VERSION 5.8 ;
BUSBITCHARS "[]" ;
DIVIDERCHAR "/" ;
UNITS
    DATABASE MICRONS 1000 ;
END UNITS

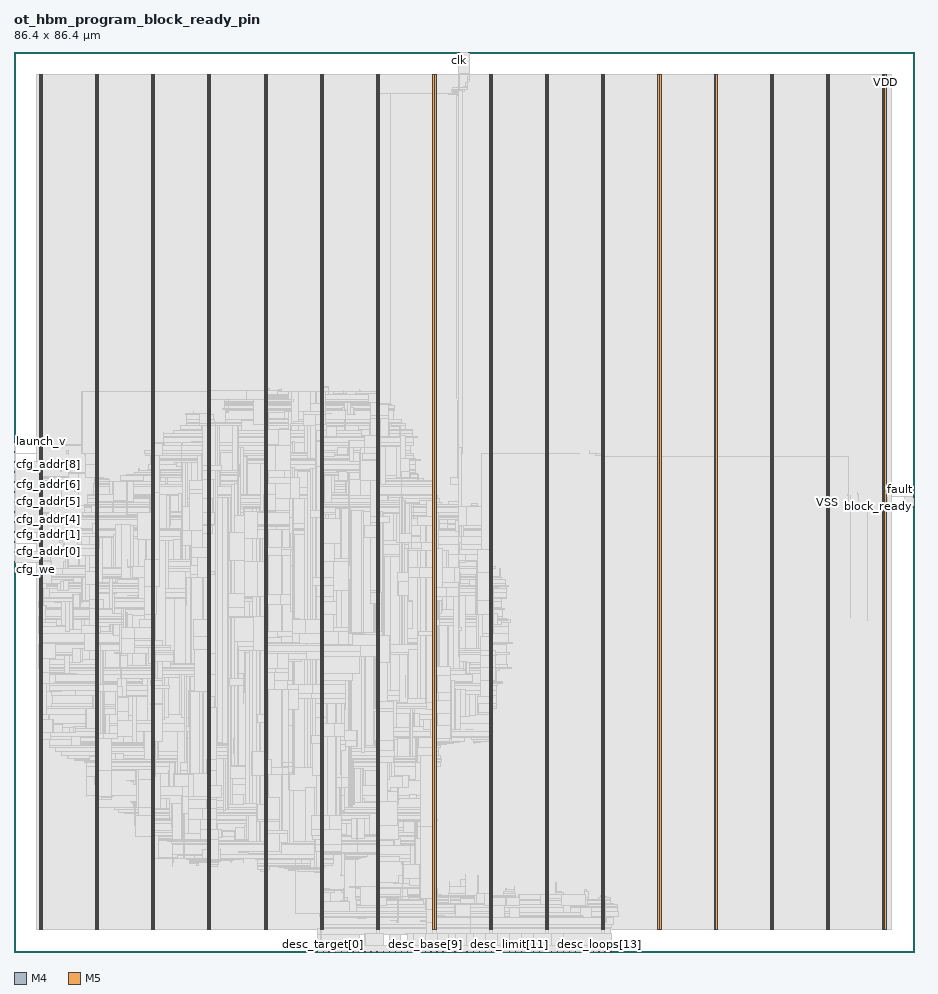
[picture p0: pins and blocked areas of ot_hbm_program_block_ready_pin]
MACRO ot_hbm_program_block_ready_pin
  FOREIGN ot_hbm_program_block_ready_pin 0 0 ;
  CLASS BLOCK ;
  SIZE 86.4 BY 86.4 ;
  PIN block_ready
    DIRECTION OUTPUT ;
    USE SIGNAL ;
    PORT
      LAYER M4 ;
        RECT  86.316 42.72 86.4 42.744 ;
    END
  END block_ready
  PIN cfg_addr[0]
    DIRECTION INPUT ;
    USE SIGNAL ;
    PORT
      LAYER M4 ;
        RECT  0 38.4 0.084 38.424 ;
    END
  END cfg_addr[0]
  PIN cfg_addr[1]
    DIRECTION INPUT ;
    USE SIGNAL ;
    PORT
      LAYER M4 ;
        RECT  0 39.36 0.084 39.384 ;
    END
  END cfg_addr[1]
  PIN cfg_addr[2]
    DIRECTION INPUT ;
    USE SIGNAL ;
    PORT
      LAYER M4 ;
        RECT  0 40.32 0.084 40.344 ;
    END
  END cfg_addr[2]
  PIN cfg_addr[3]
    DIRECTION INPUT ;
    USE SIGNAL ;
    PORT
      LAYER M4 ;
        RECT  0 41.28 0.084 41.304 ;
    END
  END cfg_addr[3]
  PIN cfg_addr[4]
    DIRECTION INPUT ;
    USE SIGNAL ;
    PORT
      LAYER M4 ;
        RECT  0 42.24 0.084 42.264 ;
    END
  END cfg_addr[4]
  PIN cfg_addr[5]
    DIRECTION INPUT ;
    USE SIGNAL ;
    PORT
      LAYER M4 ;
        RECT  0 43.2 0.084 43.224 ;
    END
  END cfg_addr[5]
  PIN cfg_addr[6]
    DIRECTION INPUT ;
    USE SIGNAL ;
    PORT
      LAYER M4 ;
        RECT  0 44.16 0.084 44.184 ;
    END
  END cfg_addr[6]
  PIN cfg_addr[7]
    DIRECTION INPUT ;
    USE SIGNAL ;
    PORT
      LAYER M4 ;
        RECT  0 45.12 0.084 45.144 ;
    END
  END cfg_addr[7]
  PIN cfg_addr[8]
    DIRECTION INPUT ;
    USE SIGNAL ;
    PORT
      LAYER M4 ;
        RECT  0 46.08 0.084 46.104 ;
    END
  END cfg_addr[8]
  PIN cfg_addr[9]
    DIRECTION INPUT ;
    USE SIGNAL ;
    PORT
      LAYER M4 ;
        RECT  0 47.04 0.084 47.064 ;
    END
  END cfg_addr[9]
  PIN cfg_we
    DIRECTION INPUT ;
    USE SIGNAL ;
    PORT
      LAYER M4 ;
        RECT  0 37.44 0.084 37.464 ;
    END
  END cfg_we
  PIN clk
    DIRECTION INPUT ;
    USE SIGNAL ;
    PORT
      LAYER M5 ;
        RECT  42.72 86.316 42.744 86.4 ;
    END
  END clk
  PIN desc_base[0]
    DIRECTION INPUT ;
    USE SIGNAL ;
    PORT
      LAYER M5 ;
        RECT  34.272 0 34.296 0.084 ;
    END
  END desc_base[0]
  PIN desc_base[10]
    DIRECTION INPUT ;
    USE SIGNAL ;
    PORT
      LAYER M5 ;
        RECT  40.032 0 40.056 0.084 ;
    END
  END desc_base[10]
  PIN desc_base[11]
    DIRECTION INPUT ;
    USE SIGNAL ;
    PORT
      LAYER M5 ;
        RECT  40.608 0 40.632 0.084 ;
    END
  END desc_base[11]
  PIN desc_base[1]
    DIRECTION INPUT ;
    USE SIGNAL ;
    PORT
      LAYER M5 ;
        RECT  34.848 0 34.872 0.084 ;
    END
  END desc_base[1]
  PIN desc_base[2]
    DIRECTION INPUT ;
    USE SIGNAL ;
    PORT
      LAYER M5 ;
        RECT  35.424 0 35.448 0.084 ;
    END
  END desc_base[2]
  PIN desc_base[3]
    DIRECTION INPUT ;
    USE SIGNAL ;
    PORT
      LAYER M5 ;
        RECT  36 0 36.024 0.084 ;
    END
  END desc_base[3]
  PIN desc_base[4]
    DIRECTION INPUT ;
    USE SIGNAL ;
    PORT
      LAYER M5 ;
        RECT  36.576 0 36.6 0.084 ;
    END
  END desc_base[4]
  PIN desc_base[5]
    DIRECTION INPUT ;
    USE SIGNAL ;
    PORT
      LAYER M5 ;
        RECT  37.152 0 37.176 0.084 ;
    END
  END desc_base[5]
  PIN desc_base[6]
    DIRECTION INPUT ;
    USE SIGNAL ;
    PORT
      LAYER M5 ;
        RECT  37.728 0 37.752 0.084 ;
    END
  END desc_base[6]
  PIN desc_base[7]
    DIRECTION INPUT ;
    USE SIGNAL ;
    PORT
      LAYER M5 ;
        RECT  38.304 0 38.328 0.084 ;
    END
  END desc_base[7]
  PIN desc_base[8]
    DIRECTION INPUT ;
    USE SIGNAL ;
    PORT
      LAYER M5 ;
        RECT  38.88 0 38.904 0.084 ;
    END
  END desc_base[8]
  PIN desc_base[9]
    DIRECTION INPUT ;
    USE SIGNAL ;
    PORT
      LAYER M5 ;
        RECT  39.456 0 39.48 0.084 ;
    END
  END desc_base[9]
  PIN desc_limit[0]
    DIRECTION INPUT ;
    USE SIGNAL ;
    PORT
      LAYER M5 ;
        RECT  41.184 0 41.208 0.084 ;
    END
  END desc_limit[0]
  PIN desc_limit[10]
    DIRECTION INPUT ;
    USE SIGNAL ;
    PORT
      LAYER M5 ;
        RECT  46.944 0 46.968 0.084 ;
    END
  END desc_limit[10]
  PIN desc_limit[11]
    DIRECTION INPUT ;
    USE SIGNAL ;
    PORT
      LAYER M5 ;
        RECT  47.52 0 47.544 0.084 ;
    END
  END desc_limit[11]
  PIN desc_limit[12]
    DIRECTION INPUT ;
    USE SIGNAL ;
    PORT
      LAYER M5 ;
        RECT  48.096 0 48.12 0.084 ;
    END
  END desc_limit[12]
  PIN desc_limit[1]
    DIRECTION INPUT ;
    USE SIGNAL ;
    PORT
      LAYER M5 ;
        RECT  41.76 0 41.784 0.084 ;
    END
  END desc_limit[1]
  PIN desc_limit[2]
    DIRECTION INPUT ;
    USE SIGNAL ;
    PORT
      LAYER M5 ;
        RECT  42.336 0 42.36 0.084 ;
    END
  END desc_limit[2]
  PIN desc_limit[3]
    DIRECTION INPUT ;
    USE SIGNAL ;
    PORT
      LAYER M5 ;
        RECT  42.912 0 42.936 0.084 ;
    END
  END desc_limit[3]
  PIN desc_limit[4]
    DIRECTION INPUT ;
    USE SIGNAL ;
    PORT
      LAYER M5 ;
        RECT  43.488 0 43.512 0.084 ;
    END
  END desc_limit[4]
  PIN desc_limit[5]
    DIRECTION INPUT ;
    USE SIGNAL ;
    PORT
      LAYER M5 ;
        RECT  44.064 0 44.088 0.084 ;
    END
  END desc_limit[5]
  PIN desc_limit[6]
    DIRECTION INPUT ;
    USE SIGNAL ;
    PORT
      LAYER M5 ;
        RECT  44.64 0 44.664 0.084 ;
    END
  END desc_limit[6]
  PIN desc_limit[7]
    DIRECTION INPUT ;
    USE SIGNAL ;
    PORT
      LAYER M5 ;
        RECT  45.216 0 45.24 0.084 ;
    END
  END desc_limit[7]
  PIN desc_limit[8]
    DIRECTION INPUT ;
    USE SIGNAL ;
    PORT
      LAYER M5 ;
        RECT  45.792 0 45.816 0.084 ;
    END
  END desc_limit[8]
  PIN desc_limit[9]
    DIRECTION INPUT ;
    USE SIGNAL ;
    PORT
      LAYER M5 ;
        RECT  46.368 0 46.392 0.084 ;
    END
  END desc_limit[9]
  PIN desc_loops[0]
    DIRECTION INPUT ;
    USE SIGNAL ;
    PORT
      LAYER M5 ;
        RECT  48.672 0 48.696 0.084 ;
    END
  END desc_loops[0]
  PIN desc_loops[10]
    DIRECTION INPUT ;
    USE SIGNAL ;
    PORT
      LAYER M5 ;
        RECT  54.432 0 54.456 0.084 ;
    END
  END desc_loops[10]
  PIN desc_loops[11]
    DIRECTION INPUT ;
    USE SIGNAL ;
    PORT
      LAYER M5 ;
        RECT  55.008 0 55.032 0.084 ;
    END
  END desc_loops[11]
  PIN desc_loops[12]
    DIRECTION INPUT ;
    USE SIGNAL ;
    PORT
      LAYER M5 ;
        RECT  55.584 0 55.608 0.084 ;
    END
  END desc_loops[12]
  PIN desc_loops[13]
    DIRECTION INPUT ;
    USE SIGNAL ;
    PORT
      LAYER M5 ;
        RECT  56.16 0 56.184 0.084 ;
    END
  END desc_loops[13]
  PIN desc_loops[14]
    DIRECTION INPUT ;
    USE SIGNAL ;
    PORT
      LAYER M5 ;
        RECT  56.736 0 56.76 0.084 ;
    END
  END desc_loops[14]
  PIN desc_loops[15]
    DIRECTION INPUT ;
    USE SIGNAL ;
    PORT
      LAYER M5 ;
        RECT  57.312 0 57.336 0.084 ;
    END
  END desc_loops[15]
  PIN desc_loops[1]
    DIRECTION INPUT ;
    USE SIGNAL ;
    PORT
      LAYER M5 ;
        RECT  49.248 0 49.272 0.084 ;
    END
  END desc_loops[1]
  PIN desc_loops[2]
    DIRECTION INPUT ;
    USE SIGNAL ;
    PORT
      LAYER M5 ;
        RECT  49.824 0 49.848 0.084 ;
    END
  END desc_loops[2]
  PIN desc_loops[3]
    DIRECTION INPUT ;
    USE SIGNAL ;
    PORT
      LAYER M5 ;
        RECT  50.4 0 50.424 0.084 ;
    END
  END desc_loops[3]
  PIN desc_loops[4]
    DIRECTION INPUT ;
    USE SIGNAL ;
    PORT
      LAYER M5 ;
        RECT  50.976 0 51 0.084 ;
    END
  END desc_loops[4]
  PIN desc_loops[5]
    DIRECTION INPUT ;
    USE SIGNAL ;
    PORT
      LAYER M5 ;
        RECT  51.552 0 51.576 0.084 ;
    END
  END desc_loops[5]
  PIN desc_loops[6]
    DIRECTION INPUT ;
    USE SIGNAL ;
    PORT
      LAYER M5 ;
        RECT  52.128 0 52.152 0.084 ;
    END
  END desc_loops[6]
  PIN desc_loops[7]
    DIRECTION INPUT ;
    USE SIGNAL ;
    PORT
      LAYER M5 ;
        RECT  52.704 0 52.728 0.084 ;
    END
  END desc_loops[7]
  PIN desc_loops[8]
    DIRECTION INPUT ;
    USE SIGNAL ;
    PORT
      LAYER M5 ;
        RECT  53.28 0 53.304 0.084 ;
    END
  END desc_loops[8]
  PIN desc_loops[9]
    DIRECTION INPUT ;
    USE SIGNAL ;
    PORT
      LAYER M5 ;
        RECT  53.856 0 53.88 0.084 ;
    END
  END desc_loops[9]
  PIN desc_target[0]
    DIRECTION INPUT ;
    USE SIGNAL ;
    PORT
      LAYER M5 ;
        RECT  29.664 0 29.688 0.084 ;
    END
  END desc_target[0]
  PIN desc_target[1]
    DIRECTION INPUT ;
    USE SIGNAL ;
    PORT
      LAYER M5 ;
        RECT  30.24 0 30.264 0.084 ;
    END
  END desc_target[1]
  PIN desc_target[2]
    DIRECTION INPUT ;
    USE SIGNAL ;
    PORT
      LAYER M5 ;
        RECT  30.816 0 30.84 0.084 ;
    END
  END desc_target[2]
  PIN desc_target[3]
    DIRECTION INPUT ;
    USE SIGNAL ;
    PORT
      LAYER M5 ;
        RECT  31.392 0 31.416 0.084 ;
    END
  END desc_target[3]
  PIN desc_target[4]
    DIRECTION INPUT ;
    USE SIGNAL ;
    PORT
      LAYER M5 ;
        RECT  31.968 0 31.992 0.084 ;
    END
  END desc_target[4]
  PIN desc_target[5]
    DIRECTION INPUT ;
    USE SIGNAL ;
    PORT
      LAYER M5 ;
        RECT  32.544 0 32.568 0.084 ;
    END
  END desc_target[5]
  PIN desc_target[6]
    DIRECTION INPUT ;
    USE SIGNAL ;
    PORT
      LAYER M5 ;
        RECT  33.12 0 33.144 0.084 ;
    END
  END desc_target[6]
  PIN desc_target[7]
    DIRECTION INPUT ;
    USE SIGNAL ;
    PORT
      LAYER M5 ;
        RECT  33.696 0 33.72 0.084 ;
    END
  END desc_target[7]
  PIN desc_v
    DIRECTION INPUT ;
    USE SIGNAL ;
    PORT
      LAYER M5 ;
        RECT  29.088 0 29.112 0.084 ;
    END
  END desc_v
  PIN fault
    DIRECTION OUTPUT ;
    USE SIGNAL ;
    PORT
      LAYER M4 ;
        RECT  86.316 43.68 86.4 43.704 ;
    END
  END fault
  PIN launch_v
    DIRECTION INPUT ;
    USE SIGNAL ;
    PORT
      LAYER M4 ;
        RECT  0 48.96 0.084 48.984 ;
    END
  END launch_v
  PIN program_active
    DIRECTION INPUT ;
    USE SIGNAL ;
    PORT
      LAYER M4 ;
        RECT  0 48 0.084 48.024 ;
    END
  END program_active
  PIN rst_n
    DIRECTION INPUT ;
    USE SIGNAL ;
    PORT
      LAYER M5 ;
        RECT  43.68 86.316 43.704 86.4 ;
    END
  END rst_n
  PIN VDD
    DIRECTION INOUT ;
    USE POWER ;
    PORT
      LAYER M5 ;
        RECT  83.592 2.151 83.712 84.249 ;
        RECT  78.192 2.151 78.312 84.249 ;
        RECT  72.792 2.151 72.912 84.249 ;
        RECT  67.392 2.151 67.512 84.249 ;
        RECT  61.992 2.151 62.112 84.249 ;
        RECT  56.592 2.151 56.712 84.249 ;
        RECT  51.192 2.151 51.312 84.249 ;
        RECT  45.792 2.151 45.912 84.249 ;
        RECT  40.392 2.151 40.512 84.249 ;
        RECT  34.992 2.151 35.112 84.249 ;
        RECT  29.592 2.151 29.712 84.249 ;
        RECT  24.192 2.151 24.312 84.249 ;
        RECT  18.792 2.151 18.912 84.249 ;
        RECT  13.392 2.151 13.512 84.249 ;
        RECT  7.992 2.151 8.112 84.249 ;
        RECT  2.592 2.151 2.712 84.249 ;
    END
  END VDD
  PIN VSS
    DIRECTION INOUT ;
    USE GROUND ;
    PORT
      LAYER M5 ;
        RECT  83.4 2.137 83.52 84.263 ;
        RECT  78 2.137 78.12 84.263 ;
        RECT  72.6 2.137 72.72 84.263 ;
        RECT  67.2 2.137 67.32 84.263 ;
        RECT  61.8 2.137 61.92 84.263 ;
        RECT  56.4 2.137 56.52 84.263 ;
        RECT  51 2.137 51.12 84.263 ;
        RECT  45.6 2.137 45.72 84.263 ;
        RECT  40.2 2.137 40.32 84.263 ;
        RECT  34.8 2.137 34.92 84.263 ;
        RECT  29.4 2.137 29.52 84.263 ;
        RECT  24 2.137 24.12 84.263 ;
        RECT  18.6 2.137 18.72 84.263 ;
        RECT  13.2 2.137 13.32 84.263 ;
        RECT  7.8 2.137 7.92 84.263 ;
        RECT  2.4 2.137 2.52 84.263 ;
    END
  END VSS
  # OT_OBS_CLOSED layer=M5 d_um=1.536 added=181
  OBS
    LAYER RVTN ;
     RECT  2.16 2.16 84.24 2.295 ;
     RECT  2.16 2.565 84.24 2.835 ;
     RECT  2.16 3.105 84.24 3.375 ;
     RECT  2.16 3.645 84.24 3.915 ;
     RECT  2.16 4.185 84.24 4.455 ;
     RECT  2.16 4.725 84.24 4.995 ;
     RECT  2.16 5.265 84.24 5.535 ;
     RECT  2.16 5.805 84.24 6.075 ;
     RECT  2.16 6.345 84.24 6.615 ;
     RECT  2.16 6.885 84.24 7.155 ;
     RECT  2.16 7.425 84.24 7.695 ;
     RECT  2.16 7.965 84.24 8.235 ;
     RECT  2.16 8.505 84.24 8.775 ;
     RECT  2.16 9.045 84.24 9.315 ;
     RECT  2.16 9.585 84.24 9.855 ;
     RECT  2.16 10.125 84.24 10.395 ;
     RECT  2.16 10.665 84.24 10.935 ;
     RECT  2.16 11.205 84.24 11.475 ;
     RECT  2.16 11.745 84.24 12.015 ;
     RECT  2.16 12.285 84.24 12.555 ;
     RECT  2.16 12.825 84.24 13.095 ;
     RECT  2.16 13.365 84.24 13.635 ;
     RECT  2.16 13.905 84.24 14.175 ;
     RECT  2.16 14.445 84.24 14.715 ;
     RECT  2.16 14.985 84.24 15.255 ;
     RECT  2.16 15.525 84.24 15.795 ;
     RECT  2.16 16.065 84.24 16.335 ;
     RECT  2.16 16.605 84.24 16.875 ;
     RECT  2.16 17.145 84.24 17.415 ;
     RECT  2.16 17.685 84.24 17.955 ;
     RECT  2.16 18.225 84.24 18.495 ;
     RECT  2.16 18.765 84.24 19.035 ;
     RECT  2.16 19.305 84.24 19.575 ;
     RECT  2.16 19.845 84.24 20.115 ;
     RECT  2.16 20.385 84.24 20.655 ;
     RECT  2.16 20.925 84.24 21.195 ;
     RECT  2.16 21.465 84.24 21.735 ;
     RECT  2.16 22.005 84.24 22.275 ;
     RECT  2.16 22.545 84.24 22.815 ;
     RECT  2.16 23.085 84.24 23.355 ;
     RECT  2.16 23.625 84.24 23.895 ;
     RECT  2.16 24.165 84.24 24.435 ;
     RECT  2.16 24.705 84.24 24.975 ;
     RECT  2.16 25.245 84.24 25.515 ;
     RECT  2.16 25.785 84.24 26.055 ;
     RECT  2.16 26.325 84.24 26.595 ;
     RECT  2.16 26.865 84.24 27.135 ;
     RECT  2.16 27.405 84.24 27.675 ;
     RECT  2.16 27.945 84.24 28.215 ;
     RECT  2.16 28.485 84.24 28.755 ;
     RECT  2.16 29.025 84.24 29.295 ;
     RECT  2.16 29.565 84.24 29.835 ;
     RECT  2.16 30.105 84.24 30.375 ;
     RECT  2.16 30.645 84.24 30.915 ;
     RECT  2.16 31.185 84.24 31.455 ;
     RECT  2.16 31.725 84.24 31.995 ;
     RECT  2.16 32.265 84.24 32.535 ;
     RECT  2.16 32.805 84.24 33.075 ;
     RECT  2.16 33.345 84.24 33.615 ;
     RECT  2.16 33.885 84.24 34.155 ;
     RECT  2.16 34.425 84.24 34.695 ;
     RECT  2.16 34.965 84.24 35.235 ;
     RECT  2.16 35.505 84.24 35.775 ;
     RECT  2.16 36.045 84.24 36.315 ;
     RECT  2.16 36.585 84.24 36.855 ;
     RECT  2.16 37.125 84.24 37.395 ;
     RECT  2.16 37.665 84.24 37.935 ;
     RECT  2.16 38.205 84.24 38.475 ;
     RECT  2.16 38.745 84.24 39.015 ;
     RECT  2.16 39.285 84.24 39.555 ;
     RECT  2.16 39.825 84.24 40.095 ;
     RECT  2.16 40.365 84.24 40.635 ;
     RECT  2.16 40.905 84.24 41.175 ;
     RECT  2.16 41.445 84.24 41.715 ;
     RECT  2.16 41.985 84.24 42.255 ;
     RECT  2.16 42.525 84.24 42.795 ;
     RECT  2.16 43.065 84.24 43.335 ;
     RECT  2.16 43.605 84.24 43.875 ;
     RECT  2.16 44.145 84.24 44.415 ;
     RECT  2.16 44.685 84.24 44.955 ;
     RECT  2.16 45.225 84.24 45.495 ;
     RECT  2.16 45.765 84.24 46.035 ;
     RECT  2.16 46.305 84.24 46.575 ;
     RECT  2.16 46.845 84.24 47.115 ;
     RECT  2.16 47.385 84.24 47.655 ;
     RECT  2.16 47.925 84.24 48.195 ;
     RECT  2.16 48.465 84.24 48.735 ;
     RECT  2.16 49.005 84.24 49.275 ;
     RECT  2.16 49.545 84.24 49.815 ;
     RECT  2.16 50.085 84.24 50.355 ;
     RECT  2.16 50.625 84.24 50.895 ;
     RECT  2.16 51.165 84.24 51.435 ;
     RECT  2.16 51.705 84.24 51.975 ;
     RECT  2.16 52.245 84.24 52.515 ;
     RECT  2.16 52.785 84.24 53.055 ;
     RECT  2.16 53.325 84.24 53.595 ;
     RECT  2.16 53.865 84.24 54.135 ;
     RECT  2.16 54.405 84.24 54.675 ;
     RECT  2.16 54.945 84.24 55.215 ;
     RECT  2.16 55.485 84.24 55.755 ;
     RECT  2.16 56.025 84.24 56.295 ;
     RECT  2.16 56.565 84.24 56.835 ;
     RECT  2.16 57.105 84.24 57.375 ;
     RECT  2.16 57.645 84.24 57.915 ;
     RECT  2.16 58.185 84.24 58.455 ;
     RECT  2.16 58.725 84.24 58.995 ;
     RECT  2.16 59.265 84.24 59.535 ;
     RECT  2.16 59.805 84.24 60.075 ;
     RECT  2.16 60.345 84.24 60.615 ;
     RECT  2.16 60.885 84.24 61.155 ;
     RECT  2.16 61.425 84.24 61.695 ;
     RECT  2.16 61.965 84.24 62.235 ;
     RECT  2.16 62.505 84.24 62.775 ;
     RECT  2.16 63.045 84.24 63.315 ;
     RECT  2.16 63.585 84.24 63.855 ;
     RECT  2.16 64.125 84.24 64.395 ;
     RECT  2.16 64.665 84.24 64.935 ;
     RECT  2.16 65.205 84.24 65.475 ;
     RECT  2.16 65.745 84.24 66.015 ;
     RECT  2.16 66.285 84.24 66.555 ;
     RECT  2.16 66.825 84.24 67.095 ;
     RECT  2.16 67.365 84.24 67.635 ;
     RECT  2.16 67.905 84.24 68.175 ;
     RECT  2.16 68.445 84.24 68.715 ;
     RECT  2.16 68.985 84.24 69.255 ;
     RECT  2.16 69.525 84.24 69.795 ;
     RECT  2.16 70.065 84.24 70.335 ;
     RECT  2.16 70.605 84.24 70.875 ;
     RECT  2.16 71.145 84.24 71.415 ;
     RECT  2.16 71.685 84.24 71.955 ;
     RECT  2.16 72.225 84.24 72.495 ;
     RECT  2.16 72.765 84.24 73.035 ;
     RECT  2.16 73.305 84.24 73.575 ;
     RECT  2.16 73.845 84.24 74.115 ;
     RECT  2.16 74.385 84.24 74.655 ;
     RECT  2.16 74.925 84.24 75.195 ;
     RECT  2.16 75.465 84.24 75.735 ;
     RECT  2.16 76.005 84.24 76.275 ;
     RECT  2.16 76.545 84.24 76.815 ;
     RECT  2.16 77.085 84.24 77.355 ;
     RECT  2.16 77.625 84.24 77.895 ;
     RECT  2.16 78.165 84.24 78.435 ;
     RECT  2.16 78.705 84.24 78.975 ;
     RECT  2.16 79.245 84.24 79.515 ;
     RECT  2.16 79.785 84.24 80.055 ;
     RECT  2.16 80.325 84.24 80.595 ;
     RECT  2.16 80.865 84.24 81.135 ;
     RECT  2.16 81.405 84.24 81.675 ;
     RECT  2.16 81.945 84.24 82.215 ;
     RECT  2.16 82.485 84.24 82.755 ;
     RECT  2.16 83.025 84.24 83.295 ;
     RECT  2.16 83.565 84.24 83.835 ;
     RECT  2.16 84.105 84.24 84.24 ;
    LAYER RVTP ;
     RECT  2.16 2.295 84.24 2.565 ;
     RECT  2.16 2.835 84.24 3.105 ;
     RECT  2.16 3.375 84.24 3.645 ;
     RECT  2.16 3.915 84.24 4.185 ;
     RECT  2.16 4.455 84.24 4.725 ;
     RECT  2.16 4.995 84.24 5.265 ;
     RECT  2.16 5.535 84.24 5.805 ;
     RECT  2.16 6.075 84.24 6.345 ;
     RECT  2.16 6.615 84.24 6.885 ;
     RECT  2.16 7.155 84.24 7.425 ;
     RECT  2.16 7.695 84.24 7.965 ;
     RECT  2.16 8.235 84.24 8.505 ;
     RECT  2.16 8.775 84.24 9.045 ;
     RECT  2.16 9.315 84.24 9.585 ;
     RECT  2.16 9.855 84.24 10.125 ;
     RECT  2.16 10.395 84.24 10.665 ;
     RECT  2.16 10.935 84.24 11.205 ;
     RECT  2.16 11.475 84.24 11.745 ;
     RECT  2.16 12.015 84.24 12.285 ;
     RECT  2.16 12.555 84.24 12.825 ;
     RECT  2.16 13.095 84.24 13.365 ;
     RECT  2.16 13.635 84.24 13.905 ;
     RECT  2.16 14.175 84.24 14.445 ;
     RECT  2.16 14.715 84.24 14.985 ;
     RECT  2.16 15.255 84.24 15.525 ;
     RECT  2.16 15.795 84.24 16.065 ;
     RECT  2.16 16.335 84.24 16.605 ;
     RECT  2.16 16.875 84.24 17.145 ;
     RECT  2.16 17.415 84.24 17.685 ;
     RECT  2.16 17.955 84.24 18.225 ;
     RECT  2.16 18.495 84.24 18.765 ;
     RECT  2.16 19.035 84.24 19.305 ;
     RECT  2.16 19.575 84.24 19.845 ;
     RECT  2.16 20.115 84.24 20.385 ;
     RECT  2.16 20.655 84.24 20.925 ;
     RECT  2.16 21.195 84.24 21.465 ;
     RECT  2.16 21.735 84.24 22.005 ;
     RECT  2.16 22.275 84.24 22.545 ;
     RECT  2.16 22.815 84.24 23.085 ;
     RECT  2.16 23.355 84.24 23.625 ;
     RECT  2.16 23.895 84.24 24.165 ;
     RECT  2.16 24.435 84.24 24.705 ;
     RECT  2.16 24.975 84.24 25.245 ;
     RECT  2.16 25.515 84.24 25.785 ;
     RECT  2.16 26.055 84.24 26.325 ;
     RECT  2.16 26.595 84.24 26.865 ;
     RECT  2.16 27.135 84.24 27.405 ;
     RECT  2.16 27.675 84.24 27.945 ;
     RECT  2.16 28.215 84.24 28.485 ;
     RECT  2.16 28.755 84.24 29.025 ;
     RECT  2.16 29.295 84.24 29.565 ;
     RECT  2.16 29.835 84.24 30.105 ;
     RECT  2.16 30.375 84.24 30.645 ;
     RECT  2.16 30.915 84.24 31.185 ;
     RECT  2.16 31.455 84.24 31.725 ;
     RECT  2.16 31.995 84.24 32.265 ;
     RECT  2.16 32.535 84.24 32.805 ;
     RECT  2.16 33.075 84.24 33.345 ;
     RECT  2.16 33.615 84.24 33.885 ;
     RECT  2.16 34.155 84.24 34.425 ;
     RECT  2.16 34.695 84.24 34.965 ;
     RECT  2.16 35.235 84.24 35.505 ;
     RECT  2.16 35.775 84.24 36.045 ;
     RECT  2.16 36.315 84.24 36.585 ;
     RECT  2.16 36.855 84.24 37.125 ;
     RECT  2.16 37.395 84.24 37.665 ;
     RECT  2.16 37.935 84.24 38.205 ;
     RECT  2.16 38.475 84.24 38.745 ;
     RECT  2.16 39.015 84.24 39.285 ;
     RECT  2.16 39.555 84.24 39.825 ;
     RECT  2.16 40.095 84.24 40.365 ;
     RECT  2.16 40.635 84.24 40.905 ;
     RECT  2.16 41.175 84.24 41.445 ;
     RECT  2.16 41.715 84.24 41.985 ;
     RECT  2.16 42.255 84.24 42.525 ;
     RECT  2.16 42.795 84.24 43.065 ;
     RECT  2.16 43.335 84.24 43.605 ;
     RECT  2.16 43.875 84.24 44.145 ;
     RECT  2.16 44.415 84.24 44.685 ;
     RECT  2.16 44.955 84.24 45.225 ;
     RECT  2.16 45.495 84.24 45.765 ;
     RECT  2.16 46.035 84.24 46.305 ;
     RECT  2.16 46.575 84.24 46.845 ;
     RECT  2.16 47.115 84.24 47.385 ;
     RECT  2.16 47.655 84.24 47.925 ;
     RECT  2.16 48.195 84.24 48.465 ;
     RECT  2.16 48.735 84.24 49.005 ;
     RECT  2.16 49.275 84.24 49.545 ;
     RECT  2.16 49.815 84.24 50.085 ;
     RECT  2.16 50.355 84.24 50.625 ;
     RECT  2.16 50.895 84.24 51.165 ;
     RECT  2.16 51.435 84.24 51.705 ;
     RECT  2.16 51.975 84.24 52.245 ;
     RECT  2.16 52.515 84.24 52.785 ;
     RECT  2.16 53.055 84.24 53.325 ;
     RECT  2.16 53.595 84.24 53.865 ;
     RECT  2.16 54.135 84.24 54.405 ;
     RECT  2.16 54.675 84.24 54.945 ;
     RECT  2.16 55.215 84.24 55.485 ;
     RECT  2.16 55.755 84.24 56.025 ;
     RECT  2.16 56.295 84.24 56.565 ;
     RECT  2.16 56.835 84.24 57.105 ;
     RECT  2.16 57.375 84.24 57.645 ;
     RECT  2.16 57.915 84.24 58.185 ;
     RECT  2.16 58.455 84.24 58.725 ;
     RECT  2.16 58.995 84.24 59.265 ;
     RECT  2.16 59.535 84.24 59.805 ;
     RECT  2.16 60.075 84.24 60.345 ;
     RECT  2.16 60.615 84.24 60.885 ;
     RECT  2.16 61.155 84.24 61.425 ;
     RECT  2.16 61.695 84.24 61.965 ;
     RECT  2.16 62.235 84.24 62.505 ;
     RECT  2.16 62.775 84.24 63.045 ;
     RECT  2.16 63.315 84.24 63.585 ;
     RECT  2.16 63.855 84.24 64.125 ;
     RECT  2.16 64.395 84.24 64.665 ;
     RECT  2.16 64.935 84.24 65.205 ;
     RECT  2.16 65.475 84.24 65.745 ;
     RECT  2.16 66.015 84.24 66.285 ;
     RECT  2.16 66.555 84.24 66.825 ;
     RECT  2.16 67.095 84.24 67.365 ;
     RECT  2.16 67.635 84.24 67.905 ;
     RECT  2.16 68.175 84.24 68.445 ;
     RECT  2.16 68.715 84.24 68.985 ;
     RECT  2.16 69.255 84.24 69.525 ;
     RECT  2.16 69.795 84.24 70.065 ;
     RECT  2.16 70.335 84.24 70.605 ;
     RECT  2.16 70.875 84.24 71.145 ;
     RECT  2.16 71.415 84.24 71.685 ;
     RECT  2.16 71.955 84.24 72.225 ;
     RECT  2.16 72.495 84.24 72.765 ;
     RECT  2.16 73.035 84.24 73.305 ;
     RECT  2.16 73.575 84.24 73.845 ;
     RECT  2.16 74.115 84.24 74.385 ;
     RECT  2.16 74.655 84.24 74.925 ;
     RECT  2.16 75.195 84.24 75.465 ;
     RECT  2.16 75.735 84.24 76.005 ;
     RECT  2.16 76.275 84.24 76.545 ;
     RECT  2.16 76.815 84.24 77.085 ;
     RECT  2.16 77.355 84.24 77.625 ;
     RECT  2.16 77.895 84.24 78.165 ;
     RECT  2.16 78.435 84.24 78.705 ;
     RECT  2.16 78.975 84.24 79.245 ;
     RECT  2.16 79.515 84.24 79.785 ;
     RECT  2.16 80.055 84.24 80.325 ;
     RECT  2.16 80.595 84.24 80.865 ;
     RECT  2.16 81.135 84.24 81.405 ;
     RECT  2.16 81.675 84.24 81.945 ;
     RECT  2.16 82.215 84.24 82.485 ;
     RECT  2.16 82.755 84.24 83.025 ;
     RECT  2.16 83.295 84.24 83.565 ;
     RECT  2.16 83.835 84.24 84.105 ;
    LAYER M1 ;
     RECT  2.16 2.151 84.24 84.249 ;
    LAYER M2 ;
     RECT  0.103 39.222 2.16 39.24 ;
     RECT  0.103 47.862 2.16 47.88 ;
     RECT  2.16 2.151 84.24 84.249 ;
     RECT  84.24 42.732 85.487 42.75 ;
     RECT  84.24 43.686 85.487 43.704 ;
    LAYER M3 ;
     RECT  29.088 0.571 33.138 1.723 ;
     RECT  34.272 0.571 34.794 1.723 ;
     RECT  36 0.571 37.062 1.723 ;
     RECT  38.772 0.571 38.79 1.723 ;
     RECT  41.076 0.571 41.094 1.723 ;
     RECT  42.804 0.571 42.822 1.723 ;
     RECT  44.532 0.571 44.55 1.723 ;
     RECT  45.792 0.571 45.81 1.723 ;
     RECT  46.872 0.571 46.89 1.723 ;
     RECT  49.14 0.571 49.158 1.723 ;
     RECT  51.948 0.571 51.966 1.723 ;
     RECT  29.088 1.723 57.222 2.291 ;
     RECT  29.376 2.291 57.222 2.371 ;
     RECT  2.415 2.143 2.505 2.413 ;
     RECT  7.815 2.143 7.905 2.413 ;
     RECT  13.215 2.143 13.305 2.413 ;
     RECT  18.615 2.143 18.705 2.413 ;
     RECT  24.015 2.143 24.105 2.413 ;
     RECT  61.815 2.143 61.905 2.413 ;
     RECT  67.215 2.143 67.305 2.413 ;
     RECT  72.615 2.143 72.705 2.413 ;
     RECT  78.015 2.143 78.105 2.413 ;
     RECT  83.415 2.143 83.505 2.413 ;
     RECT  29.376 2.371 57.402 2.641 ;
     RECT  29.376 2.641 57.582 3.299 ;
     RECT  29.376 3.299 47.61 3.341 ;
     RECT  48.492 3.299 54.63 3.371 ;
     RECT  29.376 3.341 47.574 3.451 ;
     RECT  55.476 3.299 57.582 3.451 ;
     RECT  48.492 3.371 54.558 3.479 ;
     RECT  29.34 3.451 47.574 3.725 ;
     RECT  48.492 3.479 54.414 3.749 ;
     RECT  55.476 3.451 58.014 3.875 ;
     RECT  29.415 3.725 47.574 3.911 ;
     RECT  32.904 3.911 47.574 4.225 ;
     RECT  48.492 3.749 52.722 4.225 ;
     RECT  53.46 3.749 54.414 4.225 ;
     RECT  55.476 3.875 57.906 4.225 ;
     RECT  53.46 4.225 57.906 4.379 ;
     RECT  32.904 4.225 52.722 4.531 ;
     RECT  53.604 4.379 57.906 4.541 ;
     RECT  54 4.541 57.906 4.559 ;
     RECT  54 4.559 57.51 4.649 ;
     RECT  29.415 3.911 32.166 4.829 ;
     RECT  32.904 4.531 52.83 4.919 ;
     RECT  31.32 4.829 32.022 4.955 ;
     RECT  32.904 4.919 52.722 4.955 ;
     RECT  54.648 4.649 57.294 4.955 ;
     RECT  54.756 4.955 57.222 5.069 ;
     RECT  32.904 4.955 48.186 5.071 ;
     RECT  49.392 4.955 52.722 5.117 ;
     RECT  31.644 4.955 32.022 5.189 ;
     RECT  32.76 5.071 48.186 5.189 ;
     RECT  49.896 5.117 52.722 5.189 ;
     RECT  54.756 5.069 55.134 5.189 ;
     RECT  56.124 5.069 57.222 5.189 ;
     RECT  31.644 5.189 31.95 5.225 ;
     RECT  34.092 5.189 48.186 5.309 ;
     RECT  32.76 5.189 33.318 5.357 ;
     RECT  56.268 5.189 56.862 5.369 ;
     RECT  37.8 5.309 48.186 5.459 ;
     RECT  56.268 5.369 56.697 5.459 ;
     RECT  34.092 5.309 37.062 5.495 ;
     RECT  37.8 5.459 41.022 5.495 ;
     RECT  50.364 5.189 52.722 5.495 ;
     RECT  44.388 5.459 45.897 5.531 ;
     RECT  41.76 5.459 43.362 5.639 ;
     RECT  46.944 5.459 48.186 5.639 ;
     RECT  44.388 5.531 44.658 5.645 ;
     RECT  44.46 5.645 44.658 5.648 ;
     RECT  52.02 5.495 52.722 5.729 ;
     RECT  29.415 4.829 30.366 5.737 ;
     RECT  31.644 5.225 31.662 5.737 ;
     RECT  52.02 5.729 52.578 5.765 ;
     RECT  46.944 5.639 48.042 5.801 ;
     RECT  54.792 5.189 55.134 5.801 ;
     RECT  29.415 5.737 30.726 5.881 ;
     RECT  31.464 5.737 31.662 5.881 ;
     RECT  29.415 5.881 31.662 5.999 ;
     RECT  47.232 5.801 48.042 5.999 ;
     RECT  54.792 5.801 54.918 5.999 ;
     RECT  29.415 5.999 30.546 6.035 ;
     RECT  31.464 5.999 31.662 6.035 ;
     RECT  54.792 5.999 54.81 6.035 ;
     RECT  37.8 5.495 40.626 6.071 ;
     RECT  47.232 5.999 47.25 6.071 ;
     RECT  32.76 5.357 32.778 6.079 ;
     RECT  29.415 6.035 30.294 6.107 ;
     RECT  34.815 5.495 37.062 6.115 ;
     RECT  37.8 6.071 40.59 6.115 ;
     RECT  31.644 6.035 31.662 6.143 ;
     RECT  32.76 6.079 33.498 6.151 ;
     RECT  34.815 6.115 40.59 6.179 ;
     RECT  32.22 6.151 33.498 6.269 ;
     RECT  48.024 5.999 48.042 6.269 ;
     RECT  32.22 6.269 33.03 6.305 ;
     RECT  41.796 5.639 43.362 6.305 ;
     RECT  32.22 6.305 32.778 6.317 ;
     RECT  52.02 5.765 52.038 6.647 ;
     RECT  34.815 6.179 40.554 6.719 ;
     RECT  41.796 6.305 41.814 6.809 ;
     RECT  42.84 6.305 43.362 6.989 ;
     RECT  44.46 5.648 44.55 7.349 ;
     RECT  44.46 7.349 44.478 7.385 ;
     RECT  31.356 7.321 31.374 7.421 ;
     RECT  43.344 6.989 43.362 7.421 ;
     RECT  31.68 7.483 31.698 7.619 ;
     RECT  29.415 6.107 29.697 7.627 ;
     RECT  24.015 2.413 24.297 7.735 ;
     RECT  27.936 7.699 27.954 7.735 ;
     RECT  27.936 7.735 27.99 7.771 ;
     RECT  28.836 7.627 29.697 7.771 ;
     RECT  23.616 7.735 24.297 7.897 ;
     RECT  26.352 7.861 26.37 7.897 ;
     RECT  27.252 7.771 29.697 7.897 ;
     RECT  26.352 7.897 29.697 8.041 ;
     RECT  25.92 8.041 29.697 8.131 ;
     RECT  18.615 2.413 18.897 8.167 ;
     RECT  23.4 7.897 24.534 8.251 ;
     RECT  25.416 8.131 29.826 8.251 ;
     RECT  17.676 8.275 17.694 8.311 ;
     RECT  23.4 8.251 29.826 8.311 ;
     RECT  18.615 8.167 19.494 8.437 ;
     RECT  23.4 8.311 30.546 8.491 ;
     RECT  17.496 8.311 17.694 8.509 ;
     RECT  15.192 8.239 15.21 8.545 ;
     RECT  16.812 8.509 17.694 8.545 ;
     RECT  18.615 8.437 19.638 8.545 ;
     RECT  16.812 8.545 19.638 8.671 ;
     RECT  20.844 8.581 20.862 8.671 ;
     RECT  16.812 8.671 19.818 8.779 ;
     RECT  20.736 8.671 20.862 8.779 ;
     RECT  16.812 8.779 20.862 8.815 ;
     RECT  16.812 8.815 21.078 8.851 ;
     RECT  22.032 8.581 22.05 8.851 ;
     RECT  23.4 8.491 30.654 8.851 ;
     RECT  32.76 6.317 32.778 8.851 ;
     RECT  32.472 8.851 33.03 8.923 ;
     RECT  34.815 6.719 40.497 8.969 ;
     RECT  15.192 8.545 15.354 8.977 ;
     RECT  16.524 8.851 22.05 8.977 ;
     RECT  23.22 8.851 30.654 8.977 ;
     RECT  31.752 8.923 33.03 9.013 ;
     RECT  31.752 9.013 33.282 9.085 ;
     RECT  31.752 9.085 33.786 9.121 ;
     RECT  15.192 8.977 30.654 9.319 ;
     RECT  31.752 9.121 33.93 9.319 ;
     RECT  34.815 8.969 39.474 9.319 ;
     RECT  15.192 9.319 33.93 9.391 ;
     RECT  34.668 9.319 39.474 9.391 ;
     RECT  15.192 9.391 39.474 10.327 ;
     RECT  40.215 8.969 40.497 10.327 ;
     RECT  15.192 10.327 40.497 10.435 ;
     RECT  13.215 2.413 13.497 10.597 ;
     RECT  15.12 10.435 40.497 10.597 ;
     RECT  13.215 10.597 13.878 10.741 ;
     RECT  14.688 10.597 40.497 10.741 ;
     RECT  13.215 10.741 40.497 11.131 ;
     RECT  13.104 11.131 40.497 11.171 ;
     RECT  13.215 11.171 40.497 11.479 ;
     RECT  13.215 11.479 40.554 11.669 ;
     RECT  11.664 12.139 11.682 12.209 ;
     RECT  11.988 12.217 12.402 12.361 ;
     RECT  13.215 11.669 40.497 12.361 ;
     RECT  11.988 12.361 40.497 12.631 ;
     RECT  11.988 12.631 40.626 12.749 ;
     RECT  11.988 12.749 40.497 13.099 ;
     RECT  11.592 13.099 40.497 13.297 ;
     RECT  10.944 13.297 40.497 13.333 ;
     RECT  10.584 13.333 40.497 13.369 ;
     RECT  10.008 13.369 40.497 13.639 ;
     RECT  9.684 13.639 40.497 13.837 ;
     RECT  7.815 2.413 8.097 13.909 ;
     RECT  9.18 13.837 40.497 13.909 ;
     RECT  6.948 14.917 6.966 15.061 ;
     RECT  7.815 13.909 40.497 15.061 ;
     RECT  6.948 15.061 40.497 17.761 ;
     RECT  6.948 17.761 40.518 17.851 ;
     RECT  6.948 17.851 40.95 18.193 ;
     RECT  6.768 18.193 40.95 18.301 ;
     RECT  5.796 18.427 5.814 18.499 ;
     RECT  6.768 18.301 41.022 18.499 ;
     RECT  5.796 18.499 41.022 18.563 ;
     RECT  5.796 18.563 40.95 18.571 ;
     RECT  5.148 18.571 40.95 18.859 ;
     RECT  4.572 18.859 40.95 18.869 ;
     RECT  4.572 18.869 40.77 19.237 ;
     RECT  3.96 19.237 40.77 19.615 ;
     RECT  3.42 19.615 40.77 19.651 ;
     RECT  3.42 19.651 40.95 19.841 ;
     RECT  6.336 19.841 40.95 19.885 ;
     RECT  6.336 19.885 41.49 20.011 ;
     RECT  6.336 20.011 42.21 20.107 ;
     RECT  6.336 20.107 42.246 20.119 ;
     RECT  44.172 20.011 44.19 20.119 ;
     RECT  6.336 20.119 42.498 20.155 ;
     RECT  44.172 20.119 44.442 20.155 ;
     RECT  6.336 20.155 42.75 20.191 ;
     RECT  44.1 20.155 44.802 20.191 ;
     RECT  45.615 5.531 45.897 20.191 ;
     RECT  44.1 20.191 45.897 20.353 ;
     RECT  3.42 19.841 5.49 20.429 ;
     RECT  6.336 20.191 43.218 20.587 ;
     RECT  43.956 20.353 45.897 20.587 ;
     RECT  3.528 20.429 5.49 20.659 ;
     RECT  6.336 20.587 45.897 20.659 ;
     RECT  3.528 20.659 45.897 21.191 ;
     RECT  2.415 2.413 2.697 21.883 ;
     RECT  2.415 21.883 2.934 21.929 ;
     RECT  3.708 21.191 45.897 21.937 ;
     RECT  2.415 21.929 2.697 22.795 ;
     RECT  3.42 21.937 45.897 22.795 ;
     RECT  2.415 22.795 45.897 23.395 ;
     RECT  2.415 23.395 46.278 23.597 ;
     RECT  3.6 23.597 46.278 23.819 ;
     RECT  2.415 23.597 2.697 24.619 ;
     RECT  3.708 23.819 46.278 24.637 ;
     RECT  2.415 24.619 2.754 24.781 ;
     RECT  2.415 24.781 2.898 25.099 ;
     RECT  3.636 24.637 46.278 25.099 ;
     RECT  2.415 25.099 46.278 25.591 ;
     RECT  2.415 25.591 46.422 25.745 ;
     RECT  3.852 25.745 46.422 25.753 ;
     RECT  2.415 25.745 3.114 25.853 ;
     RECT  3.852 25.753 46.89 25.853 ;
     RECT  3.96 25.853 46.89 25.979 ;
     RECT  2.415 25.853 3.078 26.671 ;
     RECT  3.96 25.979 46.35 26.671 ;
     RECT  2.415 26.671 46.35 27.031 ;
     RECT  2.415 27.031 46.602 27.211 ;
     RECT  2.376 27.211 47.718 27.329 ;
     RECT  2.376 27.329 47.358 27.635 ;
     RECT  2.376 27.635 47.286 28.561 ;
     RECT  2.376 28.561 47.538 28.787 ;
     RECT  2.376 28.787 47.286 29.489 ;
     RECT  2.415 29.489 47.286 29.605 ;
     RECT  2.415 29.605 47.826 29.759 ;
     RECT  2.415 29.759 47.502 30.577 ;
     RECT  2.34 30.577 47.502 31.217 ;
     RECT  2.376 31.217 47.502 31.621 ;
     RECT  2.376 31.621 47.646 31.919 ;
     RECT  2.376 31.919 47.286 31.991 ;
     RECT  2.376 31.991 46.854 32.237 ;
     RECT  2.415 32.237 46.854 32.881 ;
     RECT  2.415 32.881 47.106 32.999 ;
     RECT  2.415 32.999 46.782 33.115 ;
     RECT  2.34 33.115 46.782 33.629 ;
     RECT  2.415 33.629 46.782 33.925 ;
     RECT  2.415 33.925 47.286 33.989 ;
     RECT  3.42 33.989 47.286 34.501 ;
     RECT  2.415 33.989 2.697 34.891 ;
     RECT  3.42 34.501 47.322 34.891 ;
     RECT  2.415 34.891 47.322 35.041 ;
     RECT  2.415 35.041 47.43 35.231 ;
     RECT  2.415 35.231 47.214 35.357 ;
     RECT  3.6 35.357 47.214 35.807 ;
     RECT  3.6 35.807 46.782 35.969 ;
     RECT  3.6 35.969 46.674 36.005 ;
     RECT  3.6 36.005 45.897 36.239 ;
     RECT  4.68 36.239 45.897 36.779 ;
     RECT  46.656 36.005 46.674 36.779 ;
     RECT  4.752 36.779 45.897 36.859 ;
     RECT  4.752 36.859 46.242 37.049 ;
     RECT  3.6 36.239 3.618 37.363 ;
     RECT  2.415 35.357 2.697 37.435 ;
     RECT  2.304 37.435 2.697 37.471 ;
     RECT  3.456 37.363 3.618 37.471 ;
     RECT  2.304 37.471 3.618 37.472 ;
     RECT  4.752 37.049 45.954 37.472 ;
     RECT  4.824 37.472 45.954 37.499 ;
     RECT  2.415 37.472 3.618 37.589 ;
     RECT  2.415 37.589 3.474 37.625 ;
     RECT  4.932 37.499 45.954 37.661 ;
     RECT  4.932 37.661 45.897 38.129 ;
     RECT  4.932 38.129 5.166 38.407 ;
     RECT  4.788 38.407 5.166 38.543 ;
     RECT  3.456 37.625 3.474 38.551 ;
     RECT  3.42 38.551 3.618 38.669 ;
     RECT  3.42 38.669 3.438 38.705 ;
     RECT  6.048 38.129 45.897 39.083 ;
     RECT  4.788 38.543 4.806 39.245 ;
     RECT  0.108 39.217 0.126 39.389 ;
     RECT  4.392 39.289 4.626 39.479 ;
     RECT  4.392 39.479 4.41 39.515 ;
     RECT  6.048 39.083 6.498 39.865 ;
     RECT  7.272 39.083 45.897 39.865 ;
     RECT  6.048 39.865 45.897 40.441 ;
     RECT  5.472 40.441 45.897 40.595 ;
     RECT  6.048 40.595 45.897 40.703 ;
     RECT  41.616 40.703 45.897 41.009 ;
     RECT  2.415 37.625 2.697 41.215 ;
     RECT  2.304 41.215 2.697 41.251 ;
     RECT  2.304 41.251 3.15 41.309 ;
     RECT  6.048 40.703 40.842 41.485 ;
     RECT  41.616 41.009 44.478 41.485 ;
     RECT  6.048 41.485 44.478 41.755 ;
     RECT  5.904 41.755 44.478 41.791 ;
     RECT  4.536 41.251 4.698 41.909 ;
     RECT  5.904 41.791 44.802 41.909 ;
     RECT  2.415 41.309 3.15 42.061 ;
     RECT  2.415 42.061 3.438 42.179 ;
     RECT  4.896 42.061 4.914 42.179 ;
     RECT  6.552 41.909 44.478 42.179 ;
     RECT  3.42 42.179 3.438 42.215 ;
     RECT  83.415 2.413 83.697 42.421 ;
     RECT  83.415 42.421 83.898 42.521 ;
     RECT  83.415 42.521 83.862 42.601 ;
     RECT  6.768 42.179 44.478 42.719 ;
     RECT  83.232 42.601 83.862 42.719 ;
     RECT  85.464 42.715 85.482 42.755 ;
     RECT  6.768 42.719 42.966 42.797 ;
     RECT  81.9 31.801 81.918 42.799 ;
     RECT  81.9 42.799 82.314 42.835 ;
     RECT  43.776 42.719 44.478 42.863 ;
     RECT  81.72 42.835 82.602 42.893 ;
     RECT  5.832 42.859 5.85 42.989 ;
     RECT  6.768 42.797 42.678 42.989 ;
     RECT  82.296 42.893 82.602 42.989 ;
     RECT  43.92 42.863 44.478 43.061 ;
     RECT  7.092 42.989 41.022 43.169 ;
     RECT  2.415 42.179 2.697 43.195 ;
     RECT  3.636 43.141 3.978 43.259 ;
     RECT  5.976 43.141 5.994 43.259 ;
     RECT  41.76 42.989 42.678 43.259 ;
     RECT  2.304 43.195 2.697 43.295 ;
     RECT  3.96 43.259 3.978 43.295 ;
     RECT  41.832 43.259 41.85 43.295 ;
     RECT  83.415 42.719 83.862 43.501 ;
     RECT  7.092 43.169 40.842 43.529 ;
     RECT  83.415 43.501 83.898 43.601 ;
     RECT  83.415 43.601 83.697 43.681 ;
     RECT  85.464 43.672 85.482 43.709 ;
     RECT  7.092 43.529 40.626 43.799 ;
     RECT  80.28 32.071 80.298 43.799 ;
     RECT  83.376 43.681 83.697 43.799 ;
     RECT  7.092 43.799 40.554 43.901 ;
     RECT  80.1 43.843 80.118 43.901 ;
     RECT  81.072 42.961 81.09 43.907 ;
     RECT  80.964 43.915 80.982 44.069 ;
     RECT  6.156 43.681 6.174 44.221 ;
     RECT  4.536 43.645 4.554 44.339 ;
     RECT  5.76 44.221 6.174 44.375 ;
     RECT  7.668 43.901 40.554 44.681 ;
     RECT  42.66 43.259 42.678 44.851 ;
     RECT  7.668 44.681 9.378 44.879 ;
     RECT  10.152 44.681 40.554 44.879 ;
     RECT  7.668 44.879 9.198 44.987 ;
     RECT  2.415 43.295 2.697 45.115 ;
     RECT  4.284 44.419 4.302 45.149 ;
     RECT  10.152 44.879 40.497 45.149 ;
     RECT  2.304 45.115 2.697 45.185 ;
     RECT  10.224 45.149 40.497 45.221 ;
     RECT  31.968 45.221 40.497 45.265 ;
     RECT  2.415 45.185 2.697 45.301 ;
     RECT  7.74 44.987 9.198 45.329 ;
     RECT  2.415 45.301 3.51 45.419 ;
     RECT  7.74 45.329 9.054 45.419 ;
     RECT  31.968 45.265 39.294 45.419 ;
     RECT  7.74 45.419 8.622 45.527 ;
     RECT  7.74 45.527 8.514 45.563 ;
     RECT  7.74 45.563 8.097 45.581 ;
     RECT  41.94 44.851 42.678 45.599 ;
     RECT  2.415 45.419 3.366 45.629 ;
     RECT  10.224 45.221 31.158 45.725 ;
     RECT  10.836 45.725 31.158 45.869 ;
     RECT  31.968 45.419 38.826 45.869 ;
     RECT  42.552 45.599 42.678 45.869 ;
     RECT  6.156 44.375 6.174 45.959 ;
     RECT  31.968 45.869 38.718 45.959 ;
     RECT  5.22 45.595 5.238 46.018 ;
     RECT  11.52 45.869 31.158 46.031 ;
     RECT  31.968 45.959 38.538 46.075 ;
     RECT  5.364 46.111 5.382 46.229 ;
     RECT  11.988 46.031 31.158 46.229 ;
     RECT  12.78 46.229 31.158 46.237 ;
     RECT  31.932 46.075 38.538 46.237 ;
     RECT  4.5 46.111 4.518 46.265 ;
     RECT  12.78 46.237 38.538 46.265 ;
     RECT  12.816 46.265 38.538 46.337 ;
     RECT  11.988 46.229 12.006 46.409 ;
     RECT  6.876 46.747 6.894 46.805 ;
     RECT  12.924 46.337 38.538 46.805 ;
     RECT  2.415 45.629 2.697 46.921 ;
     RECT  7.056 46.921 7.074 47.039 ;
     RECT  2.415 46.921 3.258 47.075 ;
     RECT  13.104 46.805 38.538 47.191 ;
     RECT  13.104 47.191 39.006 47.309 ;
     RECT  13.104 47.309 38.538 47.345 ;
     RECT  7.815 45.581 8.097 47.461 ;
     RECT  67.215 2.413 67.497 47.551 ;
     RECT  78.015 2.413 78.297 47.551 ;
     RECT  67.104 47.551 67.497 47.597 ;
     RECT  77.904 47.551 78.297 47.597 ;
     RECT  13.104 47.345 38.358 47.659 ;
     RECT  56.415 5.459 56.697 47.659 ;
     RECT  55.8 47.659 56.697 47.821 ;
     RECT  12.6 47.659 38.358 47.848 ;
     RECT  6.732 47.731 6.75 47.849 ;
     RECT  7.524 47.461 8.097 47.849 ;
     RECT  12.492 47.848 38.358 47.849 ;
     RECT  55.26 47.821 56.697 47.849 ;
     RECT  5.184 47.731 5.202 47.857 ;
     RECT  54.252 47.821 54.27 47.885 ;
     RECT  6.552 47.851 6.57 47.891 ;
     RECT  42.552 45.869 42.57 47.899 ;
     RECT  0.108 47.857 0.126 48.029 ;
     RECT  5.004 47.857 5.202 48.119 ;
     RECT  55.26 47.849 55.278 48.119 ;
     RECT  5.004 48.119 5.022 48.155 ;
     RECT  12.492 47.849 38.034 48.191 ;
     RECT  42.552 47.899 43.002 48.461 ;
     RECT  13.215 48.191 38.034 48.631 ;
     RECT  4.356 48.661 4.518 48.701 ;
     RECT  2.415 47.075 2.697 48.901 ;
     RECT  4.5 48.701 4.518 48.929 ;
     RECT  13.215 48.631 38.394 48.929 ;
     RECT  2.415 48.901 3.15 48.937 ;
     RECT  2.304 48.937 3.15 48.989 ;
     RECT  2.415 48.989 3.15 49.001 ;
     RECT  14.364 48.929 38.394 49.351 ;
     RECT  14.364 49.351 38.754 49.469 ;
     RECT  14.364 49.469 38.286 49.739 ;
     RECT  14.364 49.739 14.382 49.883 ;
     RECT  15.336 49.739 38.286 50.081 ;
     RECT  15.984 50.081 38.286 50.117 ;
     RECT  15.984 50.117 37.566 50.573 ;
     RECT  16.524 50.573 37.566 50.729 ;
     RECT  16.524 50.729 37.242 50.819 ;
     RECT  16.524 50.819 19.278 51.089 ;
     RECT  20.304 50.819 37.242 51.089 ;
     RECT  20.304 51.089 36.81 51.125 ;
     RECT  20.304 51.125 36.558 51.161 ;
     RECT  16.524 51.089 19.134 51.629 ;
     RECT  16.452 51.637 16.47 51.677 ;
     RECT  17.244 51.629 18.897 51.677 ;
     RECT  17.244 51.677 17.406 51.725 ;
     RECT  18.252 51.677 18.897 51.725 ;
     RECT  17.244 51.725 17.262 51.935 ;
     RECT  20.304 51.161 36.45 52.015 ;
     RECT  20.304 52.015 36.486 52.051 ;
     RECT  20.052 52.051 36.486 52.205 ;
     RECT  20.196 52.205 36.486 52.439 ;
     RECT  20.196 52.439 36.27 52.583 ;
     RECT  20.196 52.583 36.09 52.637 ;
     RECT  20.196 52.637 35.298 52.709 ;
     RECT  20.196 52.709 35.154 52.889 ;
     RECT  36.072 52.637 36.09 52.889 ;
     RECT  42.552 48.461 42.57 52.979 ;
     RECT  20.196 52.889 35.097 53.083 ;
     RECT  19.692 53.083 35.097 53.087 ;
     RECT  19.692 53.087 27.738 53.123 ;
     RECT  20.34 53.123 27.738 53.249 ;
     RECT  20.34 53.249 21.078 53.285 ;
     RECT  22.248 53.249 27.414 53.321 ;
     RECT  22.248 53.321 26.802 53.429 ;
     RECT  20.916 53.285 20.934 53.519 ;
     RECT  22.248 53.429 22.266 53.519 ;
     RECT  28.476 53.087 35.097 53.519 ;
     RECT  28.476 53.519 31.914 53.591 ;
     RECT  29.088 53.591 31.914 53.627 ;
     RECT  29.268 53.627 31.914 53.663 ;
     RECT  32.76 53.519 35.097 53.663 ;
     RECT  23.112 53.429 26.442 53.789 ;
     RECT  29.412 53.663 30.69 53.789 ;
     RECT  32.796 53.663 35.097 53.789 ;
     RECT  23.904 53.789 25.974 53.825 ;
     RECT  29.412 53.789 30.186 53.825 ;
     RECT  32.796 53.789 33.606 53.825 ;
     RECT  24.015 53.825 25.722 53.837 ;
     RECT  31.608 53.663 31.914 53.837 ;
     RECT  32.796 53.825 33.282 53.837 ;
     RECT  31.608 53.837 31.626 53.861 ;
     RECT  33.192 53.837 33.282 53.861 ;
     RECT  25.236 53.837 25.722 53.933 ;
     RECT  25.416 53.933 25.722 53.969 ;
     RECT  33.192 53.861 33.21 53.969 ;
     RECT  24.015 53.837 24.498 54.059 ;
     RECT  25.704 53.969 25.722 54.059 ;
     RECT  29.415 53.825 30.15 54.329 ;
     RECT  42.48 53.131 42.498 82.219 ;
     RECT  42.444 82.219 42.498 82.255 ;
     RECT  42.444 82.255 42.93 82.291 ;
     RECT  41.76 82.291 42.93 82.408 ;
     RECT  41.544 82.408 42.93 82.445 ;
     RECT  42.048 82.445 42.93 82.525 ;
     RECT  42.048 82.525 42.966 82.651 ;
     RECT  42.048 82.651 43.254 82.795 ;
     RECT  42.048 82.795 43.398 82.831 ;
     RECT  42.048 82.831 43.542 82.985 ;
     RECT  42.66 82.985 43.542 83.021 ;
     RECT  43.128 83.021 43.542 83.129 ;
     RECT  43.38 83.129 43.542 83.489 ;
     RECT  43.56 83.605 43.686 83.767 ;
     RECT  2.415 49.001 2.697 83.987 ;
     RECT  7.815 47.849 8.097 83.987 ;
     RECT  13.215 48.929 13.497 83.987 ;
     RECT  18.615 51.725 18.897 83.987 ;
     RECT  24.015 54.059 24.297 83.987 ;
     RECT  29.415 54.329 29.697 83.987 ;
     RECT  34.815 53.789 35.097 83.987 ;
     RECT  40.215 45.265 40.497 83.987 ;
     RECT  45.615 41.009 45.897 83.987 ;
     RECT  51.015 5.495 51.297 83.987 ;
     RECT  56.415 47.849 56.697 83.987 ;
     RECT  61.815 2.413 62.097 83.987 ;
     RECT  67.215 47.597 67.497 83.987 ;
     RECT  72.615 2.413 72.897 83.987 ;
     RECT  78.015 47.597 78.297 83.987 ;
     RECT  83.415 43.799 83.697 83.987 ;
     RECT  43.56 83.767 43.722 84.065 ;
     RECT  2.415 83.987 2.505 84.257 ;
     RECT  7.815 83.987 7.905 84.257 ;
     RECT  13.215 83.987 13.305 84.257 ;
     RECT  18.615 83.987 18.705 84.257 ;
     RECT  24.015 83.987 24.105 84.257 ;
     RECT  29.415 83.987 29.505 84.257 ;
     RECT  34.815 83.987 34.905 84.257 ;
     RECT  40.215 83.987 40.305 84.257 ;
     RECT  45.615 83.987 45.705 84.257 ;
     RECT  51.015 83.987 51.105 84.257 ;
     RECT  56.415 83.987 56.505 84.257 ;
     RECT  61.815 83.987 61.905 84.257 ;
     RECT  67.215 83.987 67.305 84.257 ;
     RECT  72.615 83.987 72.705 84.257 ;
     RECT  78.015 83.987 78.105 84.257 ;
     RECT  83.415 83.987 83.505 84.257 ;
     RECT  43.704 84.065 43.722 84.365 ;
    LAYER M4 ;
     RECT  0.06 37.44 0.137 48.984 ;
     RECT  2.365 32.208 2.408 32.232 ;
     RECT  2.329 33.6 2.408 33.624 ;
     RECT  0.137 37.44 2.408 38.424 ;
     RECT  0.137 40.32 2.408 47.064 ;
     RECT  0.137 48.96 2.408 48.984 ;
     RECT  2.408 2.148 2.512 84.252 ;
     RECT  2.512 2.418 2.704 83.982 ;
     RECT  2.704 33.216 2.867 33.624 ;
     RECT  2.704 31.68 3.059 32.232 ;
     RECT  2.867 33.216 3.089 33.24 ;
     RECT  2.704 34.896 3.089 35.352 ;
     RECT  2.704 20.4 3.107 23.592 ;
     RECT  2.704 24.624 3.107 26.808 ;
     RECT  3.107 20.4 3.385 22.824 ;
     RECT  3.107 25.008 3.443 26.808 ;
     RECT  3.385 20.4 3.491 22.296 ;
     RECT  3.491 21.072 3.772 22.296 ;
     RECT  3.443 26.784 3.949 26.808 ;
     RECT  3.059 31.68 4.057 31.944 ;
     RECT  3.089 35.328 4.129 35.352 ;
     RECT  3.877 29.616 4.277 29.64 ;
     RECT  4.129 34.704 4.417 35.352 ;
     RECT  3.949 26.784 4.525 26.856 ;
     RECT  4.057 31.344 4.525 31.944 ;
     RECT  3.877 33.6 4.525 33.624 ;
     RECT  3.443 25.008 4.529 25.032 ;
     RECT  3.772 21.072 4.637 21.816 ;
     RECT  2.704 36.816 4.741 36.84 ;
     RECT  4.417 34.704 4.777 35.544 ;
     RECT  4.525 26.736 4.813 26.856 ;
     RECT  2.704 28.128 4.813 28.44 ;
     RECT  4.525 31.344 4.921 33.624 ;
     RECT  4.741 36.816 4.921 37.464 ;
     RECT  4.561 18.864 5.125 18.888 ;
     RECT  5.125 18.768 5.171 18.888 ;
     RECT  4.921 36.816 5.177 38.136 ;
     RECT  2.704 45.6 5.209 45.624 ;
     RECT  5.171 18.768 5.212 18.792 ;
     RECT  5.177 36.96 5.213 37.992 ;
     RECT  4.777 34.704 5.249 35.64 ;
     RECT  5.209 45.6 5.249 46.008 ;
     RECT  4.637 21.072 5.285 21.528 ;
     RECT  4.813 26.736 5.285 28.44 ;
     RECT  4.921 30.816 5.321 33.624 ;
     RECT  5.285 27.84 5.641 28.44 ;
     RECT  5.321 30.96 5.641 33.624 ;
     RECT  5.641 30.96 5.681 34.344 ;
     RECT  5.249 35.472 5.713 35.64 ;
     RECT  5.285 21.12 5.749 21.528 ;
     RECT  4.597 25.104 5.893 25.128 ;
     RECT  5.749 21.12 5.897 21.624 ;
     RECT  5.893 24.624 5.933 25.128 ;
     RECT  5.285 26.736 6.041 26.76 ;
     RECT  5.213 37.104 6.217 37.992 ;
     RECT  6.217 37.104 6.277 38.136 ;
     RECT  5.681 33.072 6.325 34.344 ;
     RECT  4.525 41.616 6.329 41.64 ;
     RECT  6.325 33.072 6.365 34.488 ;
     RECT  5.641 27.84 6.401 29.112 ;
     RECT  6.365 33.552 6.433 34.488 ;
     RECT  5.713 35.472 6.433 35.928 ;
     RECT  5.681 30.96 6.441 31.896 ;
     RECT  4.345 48.672 6.517 48.696 ;
     RECT  6.433 33.552 6.545 35.928 ;
     RECT  6.517 47.856 6.563 48.696 ;
     RECT  6.563 47.856 6.604 47.88 ;
     RECT  6.401 27.888 6.617 29.112 ;
     RECT  6.441 30.576 6.755 31.896 ;
     RECT  6.545 33.792 6.829 35.928 ;
     RECT  6.277 37.104 6.829 38.76 ;
     RECT  5.249 45.984 6.853 46.008 ;
     RECT  5.897 21.504 6.901 21.624 ;
     RECT  5.929 23.376 6.901 23.4 ;
     RECT  6.617 28.128 7.225 29.112 ;
     RECT  5.785 18.432 7.261 18.456 ;
     RECT  5.821 42.864 7.441 42.888 ;
     RECT  6.469 40.176 7.513 40.2 ;
     RECT  6.901 21.504 7.549 23.4 ;
     RECT  5.933 24.624 7.549 24.648 ;
     RECT  6.829 33.792 7.669 38.76 ;
     RECT  6.937 16.848 7.693 16.872 ;
     RECT  7.117 20.16 7.801 20.184 ;
     RECT  7.549 21.504 7.801 24.648 ;
     RECT  7.693 16.08 7.808 16.872 ;
     RECT  7.261 18.432 7.808 18.792 ;
     RECT  7.801 20.16 7.808 24.648 ;
     RECT  6.865 26.64 7.808 26.664 ;
     RECT  7.225 28.128 7.808 29.64 ;
     RECT  6.755 31.2 7.808 31.896 ;
     RECT  7.669 33.072 7.808 38.76 ;
     RECT  7.513 40.176 7.808 41.16 ;
     RECT  7.441 42.192 7.808 42.888 ;
     RECT  7.081 43.872 7.808 43.896 ;
     RECT  6.853 45.552 7.808 46.776 ;
     RECT  6.517 53.808 7.808 53.832 ;
     RECT  7.808 2.148 7.912 84.252 ;
     RECT  7.912 2.418 8.104 83.982 ;
     RECT  8.104 16.848 8.129 29.64 ;
     RECT  8.129 16.848 8.345 29.544 ;
     RECT  8.104 30.72 8.345 31.272 ;
     RECT  8.104 14.688 8.381 15 ;
     RECT  8.345 16.848 8.489 28.968 ;
     RECT  8.104 35.472 8.525 39.768 ;
     RECT  8.489 17.472 8.597 28.968 ;
     RECT  8.597 17.472 8.62 25.704 ;
     RECT  8.62 17.472 8.669 25.32 ;
     RECT  8.597 27.312 8.741 28.968 ;
     RECT  8.669 17.472 8.769 22.824 ;
     RECT  8.345 30.816 9.169 31.272 ;
     RECT  8.104 43.68 9.169 43.896 ;
     RECT  8.104 45.168 9.169 45.192 ;
     RECT  8.769 20.112 9.173 22.824 ;
     RECT  8.104 33.024 9.205 34.44 ;
     RECT  8.525 35.472 9.205 35.88 ;
     RECT  9.169 30.816 9.281 31.464 ;
     RECT  8.381 14.688 9.349 14.808 ;
     RECT  8.525 36.912 9.349 39.768 ;
     RECT  9.349 14.688 9.389 14.952 ;
     RECT  8.769 17.472 9.395 19.08 ;
     RECT  9.205 33.024 9.421 35.88 ;
     RECT  8.104 42.192 9.421 42.216 ;
     RECT  9.169 43.68 9.421 45.192 ;
     RECT  9.281 30.816 9.493 31.416 ;
     RECT  9.421 32.544 9.497 35.88 ;
     RECT  9.421 42.192 9.533 45.192 ;
     RECT  9.493 30.48 9.565 31.416 ;
     RECT  9.349 36.912 9.565 39.816 ;
     RECT  9.389 14.928 9.569 14.952 ;
     RECT  9.497 32.544 9.605 34.44 ;
     RECT  9.173 22.8 9.709 22.824 ;
     RECT  8.669 23.808 9.709 25.32 ;
     RECT  9.565 36.912 9.745 40.056 ;
     RECT  9.497 35.472 9.749 35.88 ;
     RECT  9.395 18.48 9.785 19.08 ;
     RECT  9.533 42.192 9.785 42.216 ;
     RECT  9.605 34.416 9.821 34.44 ;
     RECT  9.709 22.8 9.889 25.32 ;
     RECT  9.749 35.52 9.965 35.88 ;
     RECT  8.741 27.36 10.141 28.968 ;
     RECT  9.565 30.432 10.141 31.416 ;
     RECT  9.889 22.8 10.213 26.28 ;
     RECT  9.605 32.544 10.285 33 ;
     RECT  9.965 35.856 10.321 35.88 ;
     RECT  9.745 36.912 10.321 41.016 ;
     RECT  10.141 27.36 10.465 31.416 ;
     RECT  10.285 32.4 10.465 33 ;
     RECT  9.785 18.48 10.469 19.032 ;
     RECT  9.173 20.112 10.469 21.768 ;
     RECT  10.465 27.36 10.721 33 ;
     RECT  10.213 22.752 10.793 26.28 ;
     RECT  10.721 27.36 10.825 32.568 ;
     RECT  9.533 43.296 10.825 45.192 ;
     RECT  10.825 42.768 10.844 45.192 ;
     RECT  10.825 27.312 10.865 32.568 ;
     RECT  10.469 18.48 10.901 18.504 ;
     RECT  10.865 27.312 10.909 32.424 ;
     RECT  10.844 42 10.931 45.192 ;
     RECT  10.931 42.192 10.937 45.192 ;
     RECT  10.789 16.464 11.149 16.488 ;
     RECT  10.321 35.856 11.153 41.016 ;
     RECT  11.185 14.448 11.257 14.472 ;
     RECT  11.257 14.4 11.329 14.472 ;
     RECT  10.909 27.504 11.333 32.424 ;
     RECT  10.469 20.16 11.365 21.768 ;
     RECT  10.793 22.752 11.365 24.552 ;
     RECT  10.937 43.296 11.441 45.192 ;
     RECT  11.153 35.856 11.477 40.968 ;
     RECT  11.329 14.256 11.509 14.472 ;
     RECT  11.149 16.368 11.509 16.488 ;
     RECT  11.441 43.68 11.513 45.192 ;
     RECT  11.509 13.92 11.581 14.472 ;
     RECT  11.581 13.104 11.612 14.472 ;
     RECT  11.509 16.08 11.689 16.488 ;
     RECT  9.395 17.472 11.689 17.496 ;
     RECT  11.612 12.144 11.699 14.472 ;
     RECT  11.699 13.92 11.761 14.472 ;
     RECT  11.689 16.08 11.761 17.496 ;
     RECT  11.365 20.16 11.801 24.552 ;
     RECT  11.477 40.752 11.843 40.968 ;
     RECT  10.861 34.224 11.869 34.248 ;
     RECT  10.937 42.192 11.881 42.216 ;
     RECT  11.869 33.936 11.941 34.248 ;
     RECT  11.477 35.856 11.941 39.672 ;
     RECT  11.761 13.92 11.987 17.496 ;
     RECT  11.843 40.848 12.089 40.968 ;
     RECT  10.793 26.256 12.157 26.28 ;
     RECT  12.157 26.208 12.337 26.28 ;
     RECT  11.801 20.16 12.409 21.144 ;
     RECT  11.513 45.168 12.445 45.192 ;
     RECT  11.509 18.528 12.481 18.552 ;
     RECT  12.481 18.48 12.517 18.552 ;
     RECT  12.409 19.536 12.517 21.144 ;
     RECT  11.333 27.504 12.661 32.328 ;
     RECT  11.941 33.936 12.661 39.672 ;
     RECT  12.661 27.504 12.733 39.672 ;
     RECT  11.801 22.224 12.841 24.552 ;
     RECT  12.337 25.632 12.841 26.28 ;
     RECT  12.877 42.192 13.021 42.216 ;
     RECT  11.513 43.68 13.021 43.704 ;
     RECT  13.021 42.192 13.057 43.704 ;
     RECT  12.733 13.296 13.201 13.32 ;
     RECT  13.057 42.192 13.201 43.944 ;
     RECT  11.653 11.136 13.208 11.16 ;
     RECT  13.201 12.816 13.208 13.32 ;
     RECT  11.987 14.4 13.208 17.496 ;
     RECT  12.517 18.48 13.208 21.144 ;
     RECT  12.841 22.224 13.208 26.28 ;
     RECT  12.733 27.504 13.208 39.816 ;
     RECT  13.201 41.712 13.208 43.944 ;
     RECT  12.445 45.168 13.208 45.768 ;
     RECT  12.481 47.856 13.208 47.88 ;
     RECT  8.104 53.808 13.208 53.832 ;
     RECT  13.208 2.148 13.312 84.252 ;
     RECT  13.312 2.418 13.504 83.982 ;
     RECT  13.504 18.144 13.565 39.528 ;
     RECT  13.565 18.144 13.619 27.912 ;
     RECT  13.619 18.48 13.817 27.912 ;
     RECT  13.817 18.48 13.889 21.144 ;
     RECT  13.504 10.608 13.907 11.16 ;
     RECT  13.504 47.664 13.997 48.792 ;
     RECT  13.504 40.704 14.003 44.136 ;
     RECT  13.504 13.824 14.105 17.16 ;
     RECT  13.504 45.168 14.105 46.344 ;
     RECT  13.817 22.32 14.285 27.912 ;
     RECT  14.285 22.32 14.429 26.376 ;
     RECT  13.997 48.768 14.429 48.792 ;
     RECT  14.105 45.168 14.569 45.576 ;
     RECT  13.565 28.944 14.573 39.528 ;
     RECT  14.105 13.824 14.609 14.76 ;
     RECT  14.003 40.704 14.645 43.944 ;
     RECT  14.569 45.024 14.753 45.576 ;
     RECT  14.105 15.936 14.785 17.16 ;
     RECT  14.429 22.56 14.789 26.376 ;
     RECT  14.573 34.944 14.789 39.528 ;
     RECT  13.504 12.816 14.929 12.84 ;
     RECT  14.609 13.824 14.929 14.712 ;
     RECT  14.785 15.936 14.929 17.4 ;
     RECT  14.929 12.816 14.933 14.712 ;
     RECT  14.645 40.704 14.969 43.8 ;
     RECT  14.969 40.944 15.005 43.8 ;
     RECT  14.285 27.36 15.041 27.912 ;
     RECT  14.933 12.816 15.073 14.232 ;
     RECT  13.907 10.848 15.253 10.872 ;
     RECT  15.073 11.856 15.253 14.232 ;
     RECT  14.789 37.68 15.289 39.528 ;
     RECT  13.997 47.664 15.293 47.688 ;
     RECT  15.041 27.696 15.361 27.912 ;
     RECT  14.573 28.944 15.361 33.96 ;
     RECT  14.929 15.936 15.395 18.216 ;
     RECT  15.395 16.368 15.433 18.216 ;
     RECT  15.433 16.368 15.541 18.264 ;
     RECT  15.433 46.8 15.613 46.968 ;
     RECT  13.504 9.024 15.649 9.048 ;
     RECT  15.541 16.368 15.685 18.312 ;
     RECT  13.889 19.296 15.685 21.144 ;
     RECT  15.005 42.288 15.829 43.8 ;
     RECT  14.789 22.8 15.901 26.376 ;
     RECT  15.289 37.68 16.009 39.624 ;
     RECT  15.829 42.288 16.045 44.04 ;
     RECT  14.753 45.216 16.045 45.576 ;
     RECT  15.613 46.656 16.045 46.968 ;
     RECT  15.541 48.912 16.069 48.936 ;
     RECT  16.009 37.68 16.076 40.344 ;
     RECT  16.045 42.192 16.076 44.04 ;
     RECT  15.253 10.848 16.079 14.232 ;
     RECT  15.901 22.8 16.081 26.616 ;
     RECT  16.081 22.656 16.117 26.616 ;
     RECT  16.076 37.68 16.153 44.04 ;
     RECT  16.045 45.216 16.153 46.968 ;
     RECT  16.079 10.848 16.163 14.952 ;
     RECT  16.069 48.672 16.193 48.936 ;
     RECT  15.649 9.024 16.268 9.288 ;
     RECT  16.163 10.848 16.268 13.8 ;
     RECT  16.268 9.024 16.355 13.8 ;
     RECT  15.685 16.368 16.405 21.144 ;
     RECT  16.117 22.56 16.405 26.616 ;
     RECT  16.153 37.68 16.481 46.968 ;
     RECT  15.361 27.696 16.501 33.96 ;
     RECT  14.789 34.944 16.501 36.504 ;
     RECT  16.405 16.368 16.589 26.616 ;
     RECT  16.481 42.192 16.697 46.968 ;
     RECT  16.355 10.848 16.739 13.8 ;
     RECT  16.163 14.928 16.837 14.952 ;
     RECT  16.589 16.368 16.841 26.472 ;
     RECT  16.481 37.68 16.883 41.016 ;
     RECT  16.501 27.696 16.909 36.504 ;
     RECT  16.883 37.68 16.909 40.488 ;
     RECT  16.837 14.928 16.945 15.288 ;
     RECT  16.841 16.368 16.945 26.424 ;
     RECT  16.193 48.912 17.053 48.936 ;
     RECT  16.697 43.584 17.057 46.968 ;
     RECT  16.909 27.696 17.065 40.488 ;
     RECT  17.053 48.912 17.093 49.032 ;
     RECT  16.697 42.192 17.165 42.6 ;
     RECT  16.355 9.024 17.341 9.288 ;
     RECT  16.441 51.648 17.377 51.672 ;
     RECT  17.057 44.64 17.593 46.968 ;
     RECT  16.945 14.928 17.809 26.424 ;
     RECT  16.739 10.848 17.845 13.368 ;
     RECT  17.165 42.528 17.953 42.6 ;
     RECT  17.057 43.584 17.953 43.656 ;
     RECT  17.593 44.64 17.989 47.688 ;
     RECT  15.973 50.544 18.044 50.568 ;
     RECT  17.845 10.8 18.053 13.368 ;
     RECT  17.809 14.832 18.097 26.424 ;
     RECT  17.065 27.696 18.097 40.392 ;
     RECT  17.341 8.976 18.133 9.288 ;
     RECT  17.953 42.528 18.133 43.656 ;
     RECT  17.989 44.64 18.133 47.736 ;
     RECT  18.053 10.8 18.169 13.8 ;
     RECT  18.097 14.832 18.169 40.392 ;
     RECT  18.044 50.064 18.169 50.568 ;
     RECT  17.377 51.648 18.169 51.72 ;
     RECT  18.133 42.528 18.205 47.736 ;
     RECT  18.205 42.528 18.277 47.832 ;
     RECT  17.093 49.008 18.277 49.032 ;
     RECT  18.169 50.064 18.277 51.72 ;
     RECT  18.277 42.528 18.493 51.72 ;
     RECT  18.493 41.952 18.601 51.72 ;
     RECT  18.133 8.976 18.608 9.816 ;
     RECT  18.169 10.8 18.608 40.392 ;
     RECT  18.601 41.664 18.608 51.72 ;
     RECT  13.504 53.808 18.608 53.832 ;
     RECT  18.608 2.148 18.712 84.252 ;
     RECT  18.712 2.418 18.904 83.982 ;
     RECT  18.904 8.88 19.289 13.368 ;
     RECT  18.904 20.112 19.333 50.76 ;
     RECT  19.289 8.88 19.505 12.264 ;
     RECT  19.333 20.112 19.505 50.568 ;
     RECT  19.505 8.88 19.619 11.784 ;
     RECT  19.505 44.688 19.757 50.568 ;
     RECT  19.619 8.88 19.829 9.816 ;
     RECT  19.757 44.688 19.829 47.928 ;
     RECT  19.619 10.992 19.937 11.784 ;
     RECT  19.505 20.112 19.969 43.656 ;
     RECT  19.937 10.992 20.045 11.544 ;
     RECT  19.289 13.344 20.077 13.368 ;
     RECT  20.077 13.344 20.113 13.608 ;
     RECT  18.904 14.592 20.113 18.552 ;
     RECT  20.113 13.344 20.153 18.552 ;
     RECT  20.153 13.584 20.261 18.552 ;
     RECT  20.261 13.68 20.509 18.552 ;
     RECT  19.969 20.064 20.509 43.656 ;
     RECT  20.437 51.84 20.579 51.864 ;
     RECT  20.509 13.68 20.585 43.656 ;
     RECT  20.585 14.208 20.801 43.656 ;
     RECT  20.801 17.904 20.905 43.656 ;
     RECT  19.829 44.688 20.905 44.856 ;
     RECT  19.829 46.224 20.977 47.928 ;
     RECT  19.757 48.96 20.977 50.568 ;
     RECT  20.801 14.208 21.017 16.68 ;
     RECT  20.905 17.904 21.121 44.856 ;
     RECT  20.045 11.136 21.193 11.544 ;
     RECT  21.193 10.848 21.301 11.544 ;
     RECT  21.121 17.904 21.445 44.952 ;
     RECT  20.977 46.224 21.445 50.568 ;
     RECT  19.829 8.88 21.485 8.904 ;
     RECT  21.445 17.904 21.521 50.568 ;
     RECT  21.521 17.904 21.539 48.984 ;
     RECT  21.539 29.712 21.593 48.984 ;
     RECT  21.593 34.8 21.701 48.456 ;
     RECT  21.701 42.576 21.773 48.456 ;
     RECT  21.521 50.064 21.877 50.568 ;
     RECT  21.593 29.712 21.881 33.72 ;
     RECT  21.017 14.208 21.989 15.144 ;
     RECT  21.773 43.92 22.061 48.456 ;
     RECT  21.301 10.848 22.093 11.976 ;
     RECT  21.773 42.576 22.141 42.792 ;
     RECT  21.989 14.256 22.237 15.144 ;
     RECT  21.017 16.128 22.237 16.68 ;
     RECT  21.539 17.904 22.237 28.728 ;
     RECT  18.904 53.088 22.273 53.928 ;
     RECT  22.061 43.92 22.277 47.592 ;
     RECT  22.093 10.848 22.309 12.12 ;
     RECT  22.277 43.968 22.385 47.592 ;
     RECT  21.589 9.6 22.489 9.624 ;
     RECT  22.309 10.848 22.489 13.128 ;
     RECT  22.237 14.256 22.561 28.728 ;
     RECT  21.881 29.712 22.561 33.624 ;
     RECT  22.561 14.256 22.849 33.624 ;
     RECT  21.701 34.8 22.849 41.592 ;
     RECT  22.141 42.576 22.849 42.6 ;
     RECT  22.489 10.608 23.324 13.128 ;
     RECT  22.849 14.256 23.324 42.6 ;
     RECT  23.324 10.608 23.533 42.6 ;
     RECT  23.533 10.608 23.677 42.744 ;
     RECT  22.385 43.968 23.677 46.872 ;
     RECT  23.389 8.256 24.008 8.28 ;
     RECT  22.489 9.504 24.008 9.624 ;
     RECT  23.677 10.608 24.008 46.872 ;
     RECT  21.877 50.064 24.008 51 ;
     RECT  22.273 53.04 24.008 53.928 ;
     RECT  24.008 2.148 24.112 84.252 ;
     RECT  24.112 2.418 24.304 83.982 ;
     RECT  24.304 47.856 24.401 51.768 ;
     RECT  24.304 10.656 24.419 46.44 ;
     RECT  24.304 8.256 25.085 8.28 ;
     RECT  24.304 53.568 25.265 53.928 ;
     RECT  25.436 9.648 25.513 9.672 ;
     RECT  24.401 47.856 25.513 50.136 ;
     RECT  25.513 47.856 25.517 50.28 ;
     RECT  25.513 9.36 25.523 9.672 ;
     RECT  24.419 10.656 25.669 46.296 ;
     RECT  25.517 47.856 25.697 48.792 ;
     RECT  25.523 9.36 25.715 9.384 ;
     RECT  25.669 10.416 25.763 46.296 ;
     RECT  25.763 18.24 25.801 46.296 ;
     RECT  24.401 51.264 25.981 51.768 ;
     RECT  25.517 50.064 26.377 50.28 ;
     RECT  25.981 51.264 26.377 51.912 ;
     RECT  25.265 53.568 26.377 53.832 ;
     RECT  25.763 10.416 26.453 17.208 ;
     RECT  25.945 8.976 26.561 9 ;
     RECT  26.377 50.064 26.593 51.912 ;
     RECT  26.377 53.04 26.593 53.832 ;
     RECT  25.801 18.24 26.705 46.536 ;
     RECT  26.453 17.04 26.773 17.208 ;
     RECT  26.705 18.24 26.773 43.56 ;
     RECT  25.697 47.952 26.773 48.792 ;
     RECT  26.453 10.416 26.849 15.528 ;
     RECT  26.773 17.04 26.849 43.56 ;
     RECT  26.849 17.04 26.885 40.056 ;
     RECT  26.705 44.64 26.921 46.536 ;
     RECT  26.773 47.952 26.921 48.984 ;
     RECT  26.341 7.872 27.059 7.896 ;
     RECT  26.809 8.928 27.059 8.952 ;
     RECT  26.921 44.64 27.173 46.2 ;
     RECT  26.593 50.064 27.353 53.832 ;
     RECT  27.565 8.88 27.637 8.904 ;
     RECT  26.885 17.76 27.853 40.056 ;
     RECT  26.849 41.184 27.853 43.56 ;
     RECT  26.921 47.952 27.889 48.936 ;
     RECT  27.353 50.064 27.889 50.712 ;
     RECT  26.849 10.656 27.997 15.528 ;
     RECT  27.853 17.76 28.213 43.56 ;
     RECT  27.173 44.64 28.213 46.104 ;
     RECT  27.889 47.952 28.213 50.712 ;
     RECT  27.637 8.496 28.429 8.904 ;
     RECT  28.213 17.76 28.429 46.104 ;
     RECT  28.213 47.424 28.453 50.712 ;
     RECT  27.353 51.888 28.453 53.832 ;
     RECT  28.429 17.76 28.645 46.392 ;
     RECT  27.997 10.656 28.844 15.816 ;
     RECT  28.429 8.112 28.885 8.904 ;
     RECT  28.844 10.416 28.885 15.816 ;
     RECT  28.645 16.992 28.94 46.392 ;
     RECT  28.453 47.424 28.94 53.832 ;
     RECT  28.94 16.992 29.005 53.832 ;
     RECT  28.885 8.112 29.041 15.816 ;
     RECT  29.005 16.896 29.041 53.832 ;
     RECT  27.013 3.696 29.408 3.72 ;
     RECT  29.041 8.112 29.408 53.832 ;
     RECT  29.408 2.148 29.512 84.252 ;
     RECT  29.512 2.418 29.704 83.982 ;
     RECT  29.704 43.152 29.765 46.008 ;
     RECT  29.704 41.136 29.873 41.976 ;
     RECT  29.704 49.536 29.987 50.616 ;
     RECT  29.704 9.504 30.053 39.864 ;
     RECT  29.704 53.52 30.179 54.216 ;
     RECT  29.873 41.184 30.227 41.976 ;
     RECT  29.704 3.696 30.377 3.72 ;
     RECT  30.053 9.504 30.515 10.344 ;
     RECT  29.765 43.152 30.521 45.768 ;
     RECT  29.704 51.696 30.521 51.72 ;
     RECT  29.704 8.496 30.665 8.52 ;
     RECT  30.179 53.52 30.665 53.832 ;
     RECT  29.704 47.616 30.737 47.976 ;
     RECT  30.521 44.112 30.809 45.768 ;
     RECT  30.053 11.76 30.841 39.864 ;
     RECT  30.227 41.232 30.841 41.976 ;
     RECT  29.987 49.536 30.953 50.424 ;
     RECT  30.841 11.76 30.989 39.912 ;
     RECT  30.737 47.808 31.093 47.976 ;
     RECT  30.989 11.76 31.201 15.768 ;
     RECT  31.201 11.568 31.237 15.768 ;
     RECT  30.841 41.232 31.237 42.6 ;
     RECT  31.237 41.04 31.309 42.6 ;
     RECT  31.237 11.28 31.385 15.768 ;
     RECT  31.385 13.296 31.427 15.768 ;
     RECT  31.345 7.392 31.429 7.416 ;
     RECT  30.989 16.752 31.453 39.912 ;
     RECT  31.309 40.896 31.453 42.6 ;
     RECT  30.985 52.032 31.525 52.056 ;
     RECT  30.697 5.952 31.628 5.976 ;
     RECT  30.515 9.504 31.669 9.528 ;
     RECT  31.525 52.032 31.705 52.248 ;
     RECT  31.628 5.088 31.715 5.976 ;
     RECT  31.628 7.488 31.715 7.512 ;
     RECT  31.427 13.536 31.763 15.768 ;
     RECT  30.953 50.064 31.765 50.424 ;
     RECT  31.669 8.928 31.781 9.528 ;
     RECT  30.809 44.112 31.813 44.376 ;
     RECT  31.765 50.064 31.852 51 ;
     RECT  31.385 11.28 31.885 12.312 ;
     RECT  31.813 44.112 31.921 45.144 ;
     RECT  30.913 46.128 31.961 46.152 ;
     RECT  31.093 47.808 32.029 48.456 ;
     RECT  31.705 52.032 32.029 52.776 ;
     RECT  31.273 3.408 32.069 3.432 ;
     RECT  31.453 16.752 32.108 42.6 ;
     RECT  31.921 43.92 32.108 45.144 ;
     RECT  31.763 13.872 32.137 15.768 ;
     RECT  32.108 16.752 32.137 45.144 ;
     RECT  32.029 47.664 32.137 48.456 ;
     RECT  32.137 13.872 32.149 45.144 ;
     RECT  32.149 13.872 32.195 46.056 ;
     RECT  32.137 47.664 32.209 49.08 ;
     RECT  32.209 47.136 32.221 49.08 ;
     RECT  32.195 13.872 32.249 42.6 ;
     RECT  32.249 13.872 32.321 42.552 ;
     RECT  32.029 51.6 32.321 52.776 ;
     RECT  31.885 11.184 32.389 12.312 ;
     RECT  32.389 10.944 32.425 12.312 ;
     RECT  32.321 13.872 32.429 42.36 ;
     RECT  32.429 13.872 32.537 18.456 ;
     RECT  32.537 14.16 32.573 18.456 ;
     RECT  32.321 51.6 32.573 52.248 ;
     RECT  32.221 47.136 32.609 48.456 ;
     RECT  32.573 51.6 32.645 51.768 ;
     RECT  32.573 14.16 32.681 17.64 ;
     RECT  32.681 14.304 32.717 17.64 ;
     RECT  32.645 51.6 32.753 51.624 ;
     RECT  30.665 53.808 32.785 53.832 ;
     RECT  32.785 53.568 32.825 53.832 ;
     RECT  32.425 10.944 32.924 12.792 ;
     RECT  32.924 10.608 33.011 12.792 ;
     RECT  31.852 50.064 33.113 50.568 ;
     RECT  32.609 47.136 33.185 47.976 ;
     RECT  29.077 0.576 33.193 0.6 ;
     RECT  32.195 43.872 33.205 46.056 ;
     RECT  33.185 47.136 33.205 47.928 ;
     RECT  33.001 4.512 33.253 4.536 ;
     RECT  32.209 6.288 33.253 6.312 ;
     RECT  32.717 14.4 33.257 17.64 ;
     RECT  33.253 4.512 33.299 6.312 ;
     RECT  33.299 4.512 33.34 5.352 ;
     RECT  32.429 19.536 33.34 42.36 ;
     RECT  33.34 19.536 33.397 28.488 ;
     RECT  33.113 50.064 33.397 50.184 ;
     RECT  33.257 14.4 33.473 17.592 ;
     RECT  33.205 43.872 33.509 47.928 ;
     RECT  33.473 15.984 33.581 17.592 ;
     RECT  33.34 29.472 33.581 42.36 ;
     RECT  33.011 10.944 33.617 12.792 ;
     RECT  33.397 19.152 33.653 28.488 ;
     RECT  33.473 14.4 33.689 14.76 ;
     RECT  33.653 19.536 33.689 28.488 ;
     RECT  33.001 3.216 33.725 3.24 ;
     RECT  33.581 15.984 33.725 17.4 ;
     RECT  33.613 1.728 33.731 1.752 ;
     RECT  33.689 19.632 33.761 28.488 ;
     RECT  32.825 53.568 34.069 53.592 ;
     RECT  34.069 52.8 34.081 53.592 ;
     RECT  33.617 11.328 34.153 12.792 ;
     RECT  33.397 49.584 34.153 50.184 ;
     RECT  33.509 43.872 34.189 43.896 ;
     RECT  34.153 49.584 34.189 50.712 ;
     RECT  34.189 49.584 34.333 51.48 ;
     RECT  33.761 19.824 34.477 28.488 ;
     RECT  33.581 29.472 34.477 42.264 ;
     RECT  34.477 19.824 34.585 42.264 ;
     RECT  34.189 43.344 34.585 43.896 ;
     RECT  33.34 4.512 34.621 4.68 ;
     RECT  34.585 19.824 34.729 43.896 ;
     RECT  34.333 49.008 34.729 51.48 ;
     RECT  34.081 52.56 34.729 53.592 ;
     RECT  33.689 14.4 34.801 14.472 ;
     RECT  33.725 16.032 34.801 17.4 ;
     RECT  34.729 19.632 34.801 43.896 ;
     RECT  34.621 4.512 34.808 5.208 ;
     RECT  31.781 9.504 34.808 9.528 ;
     RECT  34.153 11.328 34.808 13.32 ;
     RECT  34.801 14.4 34.808 17.4 ;
     RECT  34.801 19.248 34.808 43.896 ;
     RECT  33.509 44.928 34.808 47.928 ;
     RECT  34.729 49.008 34.808 53.592 ;
     RECT  34.261 0.576 34.883 0.6 ;
     RECT  34.808 2.148 34.912 84.252 ;
     RECT  34.912 2.148 35.104 83.982 ;
     RECT  35.104 44.928 35.165 51.24 ;
     RECT  35.104 16.56 35.201 20.376 ;
     RECT  35.104 21.408 35.219 42.264 ;
     RECT  35.201 16.608 35.237 20.376 ;
     RECT  35.104 10.608 35.26 13.32 ;
     RECT  35.219 21.552 35.345 42.264 ;
     RECT  35.104 14.4 35.381 15.528 ;
     RECT  35.104 52.56 35.381 52.632 ;
     RECT  35.26 10.608 35.417 12.024 ;
     RECT  35.341 1.728 35.459 1.752 ;
     RECT  35.345 21.552 35.489 42.072 ;
     RECT  35.489 21.552 35.555 37.992 ;
     RECT  35.165 44.928 35.669 48.504 ;
     RECT  35.104 4.512 35.741 5.256 ;
     RECT  35.104 43.344 35.849 43.848 ;
     RECT  35.849 43.344 35.921 43.704 ;
     RECT  35.165 49.488 35.98 51.24 ;
     RECT  35.417 10.608 36.029 11.976 ;
     RECT  35.237 16.608 36.029 18.84 ;
     RECT  35.98 49.488 36.029 50.712 ;
     RECT  35.555 25.152 36.101 37.992 ;
     RECT  35.381 14.448 36.169 15.528 ;
     RECT  35.381 52.608 36.179 52.632 ;
     RECT  36.029 16.848 36.205 18.84 ;
     RECT  35.237 19.824 36.205 20.136 ;
     RECT  36.029 50.496 36.245 50.712 ;
     RECT  36.245 50.496 36.281 50.616 ;
     RECT  35.489 39.504 36.421 42.072 ;
     RECT  36.029 11.952 36.449 11.976 ;
     RECT  35.26 13.104 36.449 13.32 ;
     RECT  36.029 10.608 36.469 10.872 ;
     RECT  36.205 16.848 36.497 20.424 ;
     RECT  36.497 16.848 36.533 17.64 ;
     RECT  36.097 3.024 36.673 3.048 ;
     RECT  35.555 21.552 36.713 24.12 ;
     RECT  36.421 39.504 36.745 42.12 ;
     RECT  35.669 45.792 36.745 48.504 ;
     RECT  36.449 11.952 36.805 13.32 ;
     RECT  36.169 14.448 36.805 15.816 ;
     RECT  35.741 5.184 36.812 5.208 ;
     RECT  36.805 11.952 36.851 15.816 ;
     RECT  36.497 18.768 36.853 20.424 ;
     RECT  36.385 6.576 36.889 6.6 ;
     RECT  36.851 14.208 36.893 15.816 ;
     RECT  36.673 2.832 36.899 3.048 ;
     RECT  36.812 4.368 36.899 5.208 ;
     RECT  36.893 14.688 36.912 15.816 ;
     RECT  36.851 11.952 36.929 12.792 ;
     RECT  36.101 29.568 36.961 37.992 ;
     RECT  36.745 39.312 36.961 42.12 ;
     RECT  36.912 14.688 36.965 14.76 ;
     RECT  36.713 23.952 37.033 24.12 ;
     RECT  36.101 25.152 37.033 28.584 ;
     RECT  36.961 29.568 37.033 42.12 ;
     RECT  35.921 43.344 37.033 43.608 ;
     RECT  35.104 8.688 37.037 9.144 ;
     RECT  36.029 49.488 37.045 49.512 ;
     RECT  36.281 50.496 37.045 50.52 ;
     RECT  36.899 5.04 37.069 5.208 ;
     RECT  37.045 49.488 37.091 50.52 ;
     RECT  36.469 10.224 37.109 10.872 ;
     RECT  36.745 45.552 37.141 48.504 ;
     RECT  37.091 49.488 37.141 49.56 ;
     RECT  35.989 0.576 37.187 0.6 ;
     RECT  37.033 29.568 37.189 43.608 ;
     RECT  37.037 8.688 37.244 8.712 ;
     RECT  37.189 29.568 37.276 43.944 ;
     RECT  36.889 6.576 37.285 7.32 ;
     RECT  37.244 8.4 37.285 8.712 ;
     RECT  36.912 15.792 37.285 15.816 ;
     RECT  36.533 16.848 37.285 16.92 ;
     RECT  36.929 11.952 37.429 12.552 ;
     RECT  37.285 6.576 37.433 8.712 ;
     RECT  37.276 29.568 37.505 43.32 ;
     RECT  37.141 45.552 37.541 49.56 ;
     RECT  37.505 39.84 37.577 43.32 ;
     RECT  37.541 45.552 37.613 47.688 ;
     RECT  37.613 45.552 37.721 47.352 ;
     RECT  37.541 49.44 37.721 49.464 ;
     RECT  37.033 23.952 37.757 28.584 ;
     RECT  37.721 45.552 37.757 46.152 ;
     RECT  37.505 29.568 37.793 38.76 ;
     RECT  37.285 15.792 37.829 16.92 ;
     RECT  37.069 5.04 37.865 5.304 ;
     RECT  37.757 24.384 37.897 28.584 ;
     RECT  36.853 18.768 37.969 20.472 ;
     RECT  36.713 21.552 37.969 22.92 ;
     RECT  37.721 47.328 38.003 47.352 ;
     RECT  37.433 6.576 38.005 7.08 ;
     RECT  36.965 14.736 38.005 14.76 ;
     RECT  37.829 16.512 38.009 16.92 ;
     RECT  37.577 39.84 38.009 43.032 ;
     RECT  37.433 8.4 38.041 8.712 ;
     RECT  37.109 10.224 38.041 10.248 ;
     RECT  37.757 45.552 38.045 46.056 ;
     RECT  37.969 18.768 38.077 22.92 ;
     RECT  38.009 40.032 38.189 43.032 ;
     RECT  38.077 18.768 38.225 23.352 ;
     RECT  37.609 1.728 38.339 1.752 ;
     RECT  38.189 42.768 38.361 43.032 ;
     RECT  38.225 21.648 38.405 23.352 ;
     RECT  38.041 8.4 38.424 10.248 ;
     RECT  37.429 11.472 38.424 12.552 ;
     RECT  38.405 21.648 38.428 23.016 ;
     RECT  38.424 8.4 38.531 12.552 ;
     RECT  38.54 17.52 38.581 17.544 ;
     RECT  38.225 18.768 38.581 20.568 ;
     RECT  38.005 14.736 38.621 15.096 ;
     RECT  38.581 17.52 38.627 20.568 ;
     RECT  38.531 8.4 38.657 8.424 ;
     RECT  38.531 9.888 38.657 12.552 ;
     RECT  38.657 10.896 38.723 12.552 ;
     RECT  38.045 45.552 38.725 45.864 ;
     RECT  37.897 24.384 38.761 29.016 ;
     RECT  37.793 30.096 38.761 38.76 ;
     RECT  38.627 17.616 38.819 20.568 ;
     RECT  38.725 45.216 38.837 45.864 ;
     RECT  38.819 20.544 38.86 20.568 ;
     RECT  38.428 21.648 38.909 22.92 ;
     RECT  38.761 0.576 38.915 0.6 ;
     RECT  38.361 43.008 38.941 43.032 ;
     RECT  37.865 5.28 38.965 5.304 ;
     RECT  38.009 16.512 38.981 16.536 ;
     RECT  38.657 9.888 39.011 9.912 ;
     RECT  38.723 11.472 39.053 12.552 ;
     RECT  38.819 17.616 39.053 18.888 ;
     RECT  38.761 24.384 39.071 38.76 ;
     RECT  38.189 40.032 39.071 41.784 ;
     RECT  38.965 5.136 39.085 5.304 ;
     RECT  38.005 6.384 39.085 7.08 ;
     RECT  39.085 5.136 39.121 7.08 ;
     RECT  39.053 11.904 39.121 12.552 ;
     RECT  38.621 14.736 39.161 14.76 ;
     RECT  39.121 5.136 39.265 7.224 ;
     RECT  38.909 21.648 39.301 22.296 ;
     RECT  39.265 4.656 39.548 7.224 ;
     RECT  39.071 24.384 39.548 41.784 ;
     RECT  38.977 2.976 39.589 3 ;
     RECT  39.548 4.08 39.589 7.224 ;
     RECT  39.548 23.952 39.589 41.784 ;
     RECT  39.589 23.28 39.625 41.784 ;
     RECT  38.941 43.008 39.625 43.32 ;
     RECT  39.301 21.36 39.985 22.296 ;
     RECT  39.589 2.832 40.021 7.224 ;
     RECT  39.337 1.728 40.208 1.752 ;
     RECT  40.021 2.832 40.208 7.368 ;
     RECT  39.121 11.904 40.208 13.032 ;
     RECT  39.053 18.144 40.208 18.888 ;
     RECT  39.985 20.4 40.208 22.296 ;
     RECT  39.625 23.28 40.208 43.32 ;
     RECT  38.837 45.216 40.208 45.24 ;
     RECT  36.133 82.416 40.208 82.44 ;
     RECT  40.208 1.728 40.312 84.252 ;
     RECT  40.312 1.728 40.504 83.982 ;
     RECT  40.504 4.656 40.529 5.544 ;
     RECT  40.504 6.672 40.565 6.696 ;
     RECT  40.504 20.112 40.565 20.424 ;
     RECT  40.504 1.728 40.643 1.752 ;
     RECT  40.504 21.744 40.643 42.216 ;
     RECT  40.643 23.28 40.673 42.216 ;
     RECT  40.673 23.28 40.787 41.16 ;
     RECT  40.787 23.28 40.835 38.712 ;
     RECT  40.787 40.944 40.853 41.16 ;
     RECT  40.835 32.544 40.997 38.712 ;
     RECT  40.997 32.736 41.069 38.712 ;
     RECT  41.069 32.784 41.171 38.712 ;
     RECT  41.171 32.784 41.177 38.52 ;
     RECT  41.065 0.576 41.219 0.6 ;
     RECT  40.504 3.456 41.321 3.48 ;
     RECT  41.177 32.88 41.555 38.52 ;
     RECT  40.673 42.192 41.573 42.216 ;
     RECT  40.504 82.416 41.573 82.44 ;
     RECT  40.643 21.744 41.605 22.248 ;
     RECT  40.835 23.28 41.605 31.368 ;
     RECT  40.529 4.656 41.677 4.776 ;
     RECT  41.555 35.424 41.717 38.52 ;
     RECT  41.605 21.744 41.753 31.368 ;
     RECT  41.753 21.744 41.825 26.232 ;
     RECT  40.565 20.112 41.845 20.184 ;
     RECT  41.677 4.656 41.861 5.304 ;
     RECT  41.861 4.656 41.893 4.68 ;
     RECT  41.845 20.112 42.001 20.52 ;
     RECT  41.825 21.744 42.001 26.04 ;
     RECT  42.001 20.112 42.005 26.04 ;
     RECT  41.753 27.216 42.217 31.368 ;
     RECT  41.555 32.88 42.217 34.2 ;
     RECT  42.005 20.112 42.257 20.136 ;
     RECT  42.005 21.408 42.293 26.04 ;
     RECT  41.893 4.56 42.332 4.68 ;
     RECT  41.641 1.728 42.371 1.752 ;
     RECT  42.332 3.696 42.373 4.68 ;
     RECT  40.853 41.136 42.397 41.16 ;
     RECT  42.293 21.408 42.401 25.272 ;
     RECT  42.373 3.408 42.419 4.68 ;
     RECT  41.717 35.424 42.725 38.184 ;
     RECT  42.217 27.216 42.755 34.2 ;
     RECT  42.755 27.216 42.761 27.912 ;
     RECT  42.725 35.424 42.833 36.408 ;
     RECT  42.419 4.56 42.865 4.68 ;
     RECT  42.401 21.408 42.869 25.224 ;
     RECT  42.865 4.56 42.905 5.112 ;
     RECT  42.793 0.576 42.947 0.6 ;
     RECT  42.757 39.312 42.949 39.336 ;
     RECT  42.397 40.368 42.949 41.448 ;
     RECT  42.929 47.904 42.956 47.928 ;
     RECT  42.949 39.312 42.995 41.448 ;
     RECT  42.956 47.904 43.013 48.456 ;
     RECT  43.013 48.432 43.043 48.456 ;
     RECT  42.037 82.656 43.043 82.68 ;
     RECT  42.995 39.888 43.121 41.448 ;
     RECT  42.761 27.216 43.153 27.864 ;
     RECT  42.725 37.44 43.301 38.184 ;
     RECT  43.301 37.584 43.331 38.184 ;
     RECT  43.153 27.12 43.333 27.864 ;
     RECT  42.869 22.608 43.373 25.224 ;
     RECT  42.755 28.944 43.373 34.2 ;
     RECT  43.121 40.944 43.429 41.448 ;
     RECT  42.888 42.768 43.429 42.792 ;
     RECT  43.429 40.944 43.475 42.792 ;
     RECT  43.333 26.736 43.481 27.864 ;
     RECT  43.121 39.888 43.481 39.912 ;
     RECT  43.475 40.944 43.517 42.024 ;
     RECT  43.481 26.736 43.697 27.816 ;
     RECT  42.419 3.408 43.724 3.432 ;
     RECT  42.833 35.424 43.729 35.784 ;
     RECT  43.373 22.608 43.733 24.696 ;
     RECT  43.649 84.336 43.733 84.36 ;
     RECT  43.697 27.744 43.805 27.816 ;
     RECT  43.724 3.216 43.811 3.432 ;
     RECT  43.517 40.944 43.949 40.968 ;
     RECT  43.697 26.736 44.053 26.76 ;
     RECT  43.369 1.728 44.099 1.752 ;
     RECT  43.297 21.36 44.129 21.384 ;
     RECT  42.905 4.656 44.161 5.112 ;
     RECT  43.373 32.448 44.341 34.2 ;
     RECT  43.729 35.232 44.341 35.784 ;
     RECT  43.733 22.704 44.345 24.696 ;
     RECT  44.161 4.656 44.377 5.448 ;
     RECT  43.373 28.944 44.377 31.224 ;
     RECT  44.341 32.448 44.377 36.12 ;
     RECT  44.377 28.944 44.437 36.12 ;
     RECT  43.331 37.584 44.437 38.04 ;
     RECT  44.345 22.8 44.561 24.696 ;
     RECT  44.437 28.944 44.561 38.664 ;
     RECT  44.561 23.04 44.579 24.696 ;
     RECT  44.521 0.576 44.675 0.6 ;
     RECT  44.579 23.328 44.737 24.696 ;
     RECT  44.053 25.824 44.737 26.76 ;
     RECT  44.377 4.656 45.205 5.64 ;
     RECT  44.737 23.328 45.241 26.76 ;
     RECT  43.805 27.792 45.241 27.816 ;
     RECT  45.097 1.728 45.251 1.752 ;
     RECT  43.811 3.408 45.608 3.432 ;
     RECT  45.205 4.512 45.608 5.64 ;
     RECT  45.241 23.328 45.608 27.816 ;
     RECT  44.561 28.944 45.608 36.936 ;
     RECT  44.561 37.968 45.608 37.992 ;
     RECT  44.917 47.856 45.608 47.88 ;
     RECT  45.608 2.148 45.712 84.252 ;
     RECT  45.781 0.576 45.865 0.6 ;
     RECT  45.712 2.148 45.904 83.982 ;
     RECT  45.904 24.432 45.965 24.744 ;
     RECT  45.904 30.624 46.019 33.864 ;
     RECT  45.904 34.896 46.019 34.968 ;
     RECT  46.019 31.44 46.037 33.096 ;
     RECT  45.965 24.432 46.073 24.456 ;
     RECT  45.904 26.112 46.211 26.136 ;
     RECT  45.904 28.464 46.259 28.968 ;
     RECT  46.259 28.464 46.3 28.488 ;
     RECT  46.037 31.44 46.397 32.472 ;
     RECT  46.249 1.728 46.403 1.752 ;
     RECT  45.904 27.312 46.433 27.336 ;
     RECT  46.019 34.944 46.469 34.968 ;
     RECT  46.397 31.44 46.757 31.848 ;
     RECT  46.861 0.576 46.979 0.6 ;
     RECT  45.904 3.312 47.117 4.68 ;
     RECT  47.117 4.512 47.18 4.68 ;
     RECT  47.18 4.512 47.267 5.208 ;
     RECT  46.757 31.824 47.369 31.848 ;
     RECT  47.267 4.512 48.469 4.68 ;
     RECT  48.469 4.512 48.515 5.496 ;
     RECT  47.437 1.728 48.707 1.752 ;
     RECT  49.129 0.576 49.283 0.6 ;
     RECT  48.515 5.088 50.533 5.496 ;
     RECT  49.705 1.728 51.008 1.752 ;
     RECT  47.117 3.312 51.008 3.336 ;
     RECT  50.533 4.56 51.008 5.496 ;
     RECT  45.904 47.856 51.008 47.88 ;
     RECT  51.008 1.728 51.112 84.252 ;
     RECT  51.112 1.728 51.304 83.982 ;
     RECT  51.304 1.728 51.587 1.752 ;
     RECT  51.937 0.576 52.163 0.6 ;
     RECT  51.304 5.184 52.513 5.496 ;
     RECT  51.304 47.856 54.281 47.88 ;
     RECT  52.513 4.512 54.857 5.496 ;
     RECT  54.857 4.512 55.073 5.064 ;
     RECT  52.621 1.728 56.408 1.752 ;
     RECT  55.073 5.04 56.408 5.064 ;
     RECT  55.789 47.664 56.408 47.688 ;
     RECT  56.408 1.728 56.512 84.252 ;
     RECT  56.512 1.728 56.704 83.982 ;
     RECT  56.704 2.88 56.765 5.064 ;
     RECT  56.765 2.88 56.819 4.152 ;
     RECT  56.819 2.88 56.873 3.432 ;
     RECT  56.704 1.728 57.347 1.752 ;
     RECT  56.873 3.408 57.521 3.432 ;
     RECT  56.704 47.568 61.808 47.592 ;
     RECT  61.808 2.148 61.912 84.252 ;
     RECT  61.912 2.418 62.104 83.982 ;
     RECT  62.104 47.568 67.208 47.592 ;
     RECT  67.208 2.148 67.312 84.252 ;
     RECT  67.312 2.418 67.504 83.982 ;
     RECT  67.504 47.568 72.608 47.592 ;
     RECT  72.608 2.148 72.712 84.252 ;
     RECT  72.712 2.418 72.904 83.982 ;
     RECT  72.904 47.568 78.008 47.592 ;
     RECT  78.008 2.148 78.112 84.252 ;
     RECT  78.112 2.418 78.304 83.982 ;
     RECT  80.06 43.872 80.147 43.896 ;
     RECT  78.304 47.568 80.147 47.592 ;
     RECT  80.101 42.864 81.749 42.888 ;
     RECT  83.408 2.148 83.512 84.252 ;
     RECT  83.512 2.418 83.704 83.982 ;
     RECT  83.704 42.72 83.873 42.744 ;
     RECT  85.453 42.72 86.364 43.704 ;
    LAYER M5 ;
     RECT  29.088 0.016 57.336 0.611 ;
     RECT  33.696 0.611 33.72 1.763 ;
     RECT  35.424 0.611 35.448 1.763 ;
     RECT  37.728 0.611 38.328 1.763 ;
     RECT  39.456 0.611 40.632 1.763 ;
     RECT  41.76 0.611 42.36 1.763 ;
     RECT  43.488 0.611 44.088 1.763 ;
     RECT  45.216 0.611 45.24 1.763 ;
     RECT  46.368 0.611 46.392 1.763 ;
     RECT  47.52 0.611 48.696 1.763 ;
     RECT  49.824 0.611 51.576 1.763 ;
     RECT  52.704 0.611 57.336 1.763 ;
     RECT  2.4 2.137 2.52 2.151 ;
     RECT  7.8 2.137 7.92 2.151 ;
     RECT  13.2 2.137 13.32 2.151 ;
     RECT  18.6 2.137 18.72 2.151 ;
     RECT  24 2.137 24.12 2.151 ;
     RECT  29.4 2.137 29.52 2.151 ;
     RECT  61.8 2.137 61.92 2.151 ;
     RECT  67.2 2.137 67.32 2.151 ;
     RECT  72.6 2.137 72.72 2.151 ;
     RECT  78 2.137 78.12 2.151 ;
     RECT  83.4 2.137 83.52 2.151 ;
     RECT  40.2 1.763 40.512 2.821 ;
     RECT  56.4 1.763 56.712 3.397 ;
     RECT  39.6 2.821 40.512 4.115 ;
     RECT  56.4 3.397 56.808 4.163 ;
     RECT  36.864 2.821 36.888 4.403 ;
     RECT  42.384 3.397 42.408 4.595 ;
     RECT  43.776 3.205 43.8 4.691 ;
     RECT  47.232 4.501 47.256 5.219 ;
     RECT  48.48 4.501 48.504 5.507 ;
     RECT  33.264 4.501 33.288 6.323 ;
     RECT  31.68 5.077 31.704 7.381 ;
     RECT  38.976 5.125 39 8.389 ;
     RECT  37.296 5.029 37.32 8.435 ;
     RECT  18.6 2.151 18.912 8.869 ;
     RECT  27.024 3.685 27.048 8.963 ;
     RECT  13.2 2.151 13.512 9.013 ;
     RECT  29.4 2.151 29.712 9.493 ;
     RECT  31.392 7.381 31.704 9.493 ;
     RECT  29.4 9.493 31.704 9.539 ;
     RECT  25.68 9.349 25.704 9.637 ;
     RECT  29.4 9.539 31.416 9.637 ;
     RECT  28.896 9.637 31.416 10.355 ;
     RECT  25.488 9.637 25.704 10.501 ;
     RECT  34.8 2.137 35.112 10.741 ;
     RECT  36.48 10.213 36.504 10.741 ;
     RECT  18.6 8.869 19.608 10.789 ;
     RECT  28.896 10.355 29.712 10.789 ;
     RECT  34.8 10.741 36.504 10.837 ;
     RECT  38.496 8.389 39 10.931 ;
     RECT  13.2 9.013 13.896 11.171 ;
     RECT  28.656 10.789 29.712 11.173 ;
     RECT  16.32 9.925 16.344 11.411 ;
     RECT  24 2.151 24.312 11.413 ;
     RECT  25.488 10.501 26.232 11.413 ;
     RECT  32.976 9.493 33 11.555 ;
     RECT  24 11.413 26.232 11.699 ;
     RECT  28.512 11.173 29.712 11.749 ;
     RECT  17.856 10.789 19.608 11.795 ;
     RECT  38.688 10.931 39 12.085 ;
     RECT  34.8 10.837 36.888 12.179 ;
     RECT  24 11.699 25.512 12.517 ;
     RECT  38.688 12.085 39.048 12.563 ;
     RECT  17.856 11.795 19.416 12.755 ;
     RECT  23.376 12.517 25.512 12.755 ;
     RECT  11.664 11.125 11.688 13.139 ;
     RECT  28.512 11.749 30.312 13.139 ;
     RECT  16.704 12.709 16.728 13.333 ;
     RECT  31.392 10.355 31.416 13.621 ;
     RECT  18.096 12.755 19.416 13.811 ;
     RECT  23.376 12.755 24.312 14.147 ;
     RECT  34.8 12.179 36.84 14.483 ;
     RECT  18.48 13.811 19.416 14.675 ;
     RECT  18.6 14.675 19.416 14.821 ;
     RECT  25.488 12.755 25.512 14.867 ;
     RECT  16.128 13.333 16.728 14.917 ;
     RECT  16.128 14.917 17.208 14.963 ;
     RECT  31.392 13.621 31.752 15.059 ;
     RECT  36.816 14.483 36.84 15.443 ;
     RECT  18.6 14.821 19.944 16.019 ;
     RECT  39.024 12.563 39.048 16.501 ;
     RECT  11.952 13.909 11.976 16.595 ;
     RECT  31.392 15.059 31.416 16.787 ;
     RECT  13.2 11.171 13.512 16.885 ;
     RECT  29.4 13.139 29.712 16.981 ;
     RECT  16.704 14.963 17.208 17.029 ;
     RECT  26.352 15.637 26.376 17.029 ;
     RECT  24 14.147 24.312 17.077 ;
     RECT  16.608 17.029 17.208 17.123 ;
     RECT  15.36 15.925 15.384 17.171 ;
     RECT  7.8 2.151 8.112 17.461 ;
     RECT  9.36 14.917 9.384 17.461 ;
     RECT  16.608 17.123 16.632 17.461 ;
     RECT  18.6 16.019 19.416 17.461 ;
     RECT  25.728 17.029 26.376 17.699 ;
     RECT  38.592 16.501 39.048 18.179 ;
     RECT  34.8 14.483 35.832 18.181 ;
     RECT  15.936 17.461 16.632 18.227 ;
     RECT  24 17.077 24.744 18.467 ;
     RECT  18.48 17.461 19.416 18.515 ;
     RECT  34.8 18.181 36.408 18.805 ;
     RECT  39.024 18.179 39.048 18.851 ;
     RECT  5.136 18.757 5.16 18.899 ;
     RECT  13.2 16.885 13.608 18.947 ;
     RECT  22.848 16.981 22.872 19.235 ;
     RECT  31.344 17.029 31.368 19.333 ;
     RECT  34.8 18.805 36.504 19.379 ;
     RECT  16.608 18.227 16.632 19.621 ;
     RECT  31.344 19.333 31.8 19.909 ;
     RECT  28.656 16.981 29.712 20.053 ;
     RECT  13.2 18.947 13.512 20.197 ;
     RECT  34.8 19.379 36.408 20.293 ;
     RECT  31.296 19.909 31.8 20.339 ;
     RECT  2.4 2.151 2.712 20.389 ;
     RECT  7.8 17.461 9.384 20.485 ;
     RECT  16.608 19.621 16.68 20.485 ;
     RECT  7.8 20.485 9.96 20.531 ;
     RECT  21.072 19.093 21.096 20.531 ;
     RECT  38.784 19.669 38.808 20.579 ;
     RECT  31.296 20.339 31.704 20.677 ;
     RECT  28.512 20.053 29.712 20.819 ;
     RECT  7.8 20.531 8.568 21.011 ;
     RECT  2.4 20.389 3.48 21.061 ;
     RECT  16.608 20.485 16.824 21.157 ;
     RECT  32.928 19.765 32.952 21.251 ;
     RECT  7.8 21.011 8.112 21.493 ;
     RECT  16.56 21.157 16.824 21.635 ;
     RECT  21.456 20.965 21.48 21.683 ;
     RECT  26.352 17.699 26.376 21.733 ;
     RECT  40.2 4.115 40.512 21.733 ;
     RECT  30.816 20.677 31.704 21.971 ;
     RECT  24 18.467 24.312 22.021 ;
     RECT  11.376 20.725 11.4 22.259 ;
     RECT  2.4 21.061 3.72 22.307 ;
     RECT  16.56 21.635 16.728 22.499 ;
     RECT  28.896 20.819 29.712 22.549 ;
     RECT  23.376 22.021 24.312 22.787 ;
     RECT  2.4 22.307 3.336 22.835 ;
     RECT  40.2 21.733 40.632 22.883 ;
     RECT  38.352 21.637 38.376 23.027 ;
     RECT  34.656 20.293 36.408 23.077 ;
     RECT  40.2 22.883 40.512 23.269 ;
     RECT  26.352 21.733 26.76 23.317 ;
     RECT  31.68 21.971 31.704 23.317 ;
     RECT  34.512 23.077 36.408 23.363 ;
     RECT  6.912 21.493 8.112 23.411 ;
     RECT  18.6 18.515 19.416 23.459 ;
     RECT  13.2 20.197 14.232 23.749 ;
     RECT  28.896 22.549 29.976 23.845 ;
     RECT  13.104 23.749 14.232 23.891 ;
     RECT  28.896 23.845 30.696 23.893 ;
     RECT  31.68 23.317 31.848 23.893 ;
     RECT  44.544 23.029 44.568 23.893 ;
     RECT  45.6 2.137 45.912 23.893 ;
     RECT  39.6 23.269 40.512 23.987 ;
     RECT  34.8 23.363 36.408 24.083 ;
     RECT  40.2 23.987 40.512 24.181 ;
     RECT  28.896 23.893 31.848 24.325 ;
     RECT  9.936 20.531 9.96 24.469 ;
     RECT  10.944 23.125 10.968 24.469 ;
     RECT  9.936 24.469 10.968 24.515 ;
     RECT  18.6 23.459 19.272 24.515 ;
     RECT  44.544 23.893 45.912 24.515 ;
     RECT  7.68 23.411 8.112 24.659 ;
     RECT  28.512 24.325 31.848 24.803 ;
     RECT  40.2 24.181 40.776 24.947 ;
     RECT  21.984 23.845 22.008 24.949 ;
     RECT  7.8 24.659 8.112 25.045 ;
     RECT  16.704 22.499 16.728 25.045 ;
     RECT  16.704 25.045 17.352 25.091 ;
     RECT  26.352 23.317 27.336 25.189 ;
     RECT  24 22.787 24.312 25.237 ;
     RECT  13.2 23.891 14.232 25.333 ;
     RECT  9.936 24.515 10.44 25.475 ;
     RECT  13.2 25.333 14.904 25.619 ;
     RECT  13.2 25.619 14.232 25.621 ;
     RECT  28.608 24.803 31.848 25.667 ;
     RECT  7.8 25.045 8.568 25.715 ;
     RECT  26.304 25.189 27.336 25.715 ;
     RECT  2.4 22.835 3.096 25.813 ;
     RECT  13.104 25.621 14.232 26.051 ;
     RECT  29.4 25.667 31.848 26.053 ;
     RECT  26.304 25.715 26.76 26.099 ;
     RECT  44.784 24.515 45.912 26.101 ;
     RECT  9.936 25.475 10.296 26.243 ;
     RECT  20.64 25.573 20.664 26.243 ;
     RECT  13.2 26.051 14.232 26.291 ;
     RECT  37.584 24.469 37.608 26.579 ;
     RECT  40.2 24.947 40.632 26.579 ;
     RECT  18.6 24.515 18.912 26.629 ;
     RECT  29.4 26.053 32.472 26.725 ;
     RECT  21.984 24.949 22.104 26.773 ;
     RECT  2.4 25.813 3.432 26.819 ;
     RECT  24 25.237 25.032 26.821 ;
     RECT  24 26.821 25.08 27.253 ;
     RECT  10.224 26.243 10.296 27.301 ;
     RECT  44.784 26.101 46.2 27.347 ;
     RECT  41.856 20.485 41.88 27.395 ;
     RECT  13.2 26.291 13.512 27.733 ;
     RECT  34.8 24.083 35.832 27.829 ;
     RECT  40.2 26.579 40.512 27.829 ;
     RECT  26.352 26.099 26.76 27.877 ;
     RECT  26.352 27.877 27.624 28.069 ;
     RECT  7.8 25.715 8.112 28.117 ;
     RECT  29.4 26.725 33.144 28.357 ;
     RECT  10.224 27.301 10.872 28.451 ;
     RECT  42.624 28.357 42.648 28.453 ;
     RECT  44.784 27.347 45.912 28.453 ;
     RECT  10.224 28.451 10.296 28.645 ;
     RECT  18.6 26.629 19.368 28.691 ;
     RECT  24 27.253 25.32 28.693 ;
     RECT  26.352 28.069 28.056 28.693 ;
     RECT  40.2 27.829 40.632 28.739 ;
     RECT  9.696 28.645 10.296 28.787 ;
     RECT  24 28.693 28.056 28.885 ;
     RECT  29.4 28.357 33.288 28.885 ;
     RECT  15.36 27.829 15.384 28.933 ;
     RECT  21.504 26.773 22.104 28.933 ;
     RECT  42.624 28.453 42.744 28.933 ;
     RECT  14.976 28.933 15.384 28.979 ;
     RECT  42.624 28.933 43.368 28.979 ;
     RECT  44.784 28.453 46.248 28.979 ;
     RECT  7.2 28.117 8.112 28.981 ;
     RECT  17.328 25.091 17.352 29.029 ;
     RECT  18.6 28.691 18.912 29.029 ;
     RECT  42.72 28.979 43.368 29.123 ;
     RECT  11.568 28.693 11.592 29.221 ;
     RECT  12.912 27.733 13.512 29.221 ;
     RECT  14.976 28.979 15 29.221 ;
     RECT  21.504 28.933 22.968 29.365 ;
     RECT  24 28.885 33.288 29.411 ;
     RECT  11.568 29.221 15 29.459 ;
     RECT  29.4 29.411 33.288 29.459 ;
     RECT  29.4 29.459 32.472 29.555 ;
     RECT  24 29.411 28.056 29.603 ;
     RECT  3.936 28.165 3.96 29.651 ;
     RECT  24 29.603 27.432 29.747 ;
     RECT  21.456 29.365 22.968 29.845 ;
     RECT  11.568 29.459 14.232 29.891 ;
     RECT  11.568 29.891 13.512 30.133 ;
     RECT  24 29.747 25.704 30.227 ;
     RECT  25.296 30.227 25.704 30.275 ;
     RECT  44.784 28.979 45.912 30.275 ;
     RECT  17.232 29.029 18.912 30.323 ;
     RECT  34.8 27.829 36.024 30.419 ;
     RECT  32.16 29.555 32.472 30.563 ;
     RECT  6.72 28.981 8.112 30.565 ;
     RECT  26.736 29.747 27.432 30.565 ;
     RECT  44.976 30.275 45.912 30.613 ;
     RECT  33.6 30.517 33.624 30.659 ;
     RECT  38.784 30.373 38.808 30.755 ;
     RECT  25.296 30.275 25.32 30.803 ;
     RECT  29.4 29.555 31.176 30.803 ;
     RECT  34.8 30.419 35.4 30.803 ;
     RECT  42.72 29.123 42.744 30.853 ;
     RECT  32.16 30.563 32.184 31.139 ;
     RECT  42.72 30.853 42.984 31.139 ;
     RECT  11.52 30.133 13.512 31.187 ;
     RECT  42.72 31.139 42.888 31.187 ;
     RECT  40.2 28.739 40.512 31.333 ;
     RECT  6.48 30.565 8.112 31.379 ;
     RECT  26.736 30.565 27.96 31.907 ;
     RECT  2.4 26.819 2.712 31.909 ;
     RECT  12.048 31.187 13.512 31.955 ;
     RECT  17.232 30.323 17.256 31.955 ;
     RECT  40.2 31.333 40.824 31.955 ;
     RECT  26.736 31.907 27.384 32.003 ;
     RECT  21.12 29.845 22.968 32.101 ;
     RECT  20.544 32.101 22.968 32.195 ;
     RECT  29.4 30.803 30.696 32.389 ;
     RECT  44.976 30.613 46.008 32.389 ;
     RECT  12.48 31.955 13.512 32.437 ;
     RECT  26.736 32.003 26.856 32.531 ;
     RECT  26.736 32.531 26.76 32.725 ;
     RECT  10.272 28.787 10.296 33.011 ;
     RECT  7.2 31.379 8.112 33.013 ;
     RECT  20.544 32.195 22.104 33.107 ;
     RECT  40.2 31.955 40.512 33.109 ;
     RECT  2.4 31.909 3.048 33.251 ;
     RECT  34.8 30.803 35.304 33.493 ;
     RECT  29.4 32.389 30.984 33.683 ;
     RECT  37.824 31.093 38.232 33.683 ;
     RECT  37.872 33.683 38.232 33.779 ;
     RECT  44.448 32.389 46.008 33.779 ;
     RECT  40.2 33.109 40.632 33.781 ;
     RECT  7.2 33.013 8.568 33.827 ;
     RECT  24 30.227 24.312 34.117 ;
     RECT  29.4 33.683 30.696 34.165 ;
     RECT  40.2 33.781 41.16 34.165 ;
     RECT  25.536 33.349 25.56 34.307 ;
     RECT  20.592 33.107 22.104 34.403 ;
     RECT  34.272 33.493 35.304 34.547 ;
     RECT  34.272 34.547 35.208 34.739 ;
     RECT  44.448 33.779 44.52 34.835 ;
     RECT  2.4 33.251 2.856 34.931 ;
     RECT  45.6 33.779 46.008 34.931 ;
     RECT  40.2 34.165 41.544 35.027 ;
     RECT  12.48 32.437 13.704 35.125 ;
     RECT  28.992 34.165 30.696 35.173 ;
     RECT  7.2 33.827 8.112 35.317 ;
     RECT  36.864 34.213 36.888 35.509 ;
     RECT  42.72 31.187 42.744 35.509 ;
     RECT  36.768 35.509 36.888 35.555 ;
     RECT  32.064 34.741 32.088 35.749 ;
     RECT  44.496 34.835 44.52 35.845 ;
     RECT  28.608 35.173 30.696 35.939 ;
     RECT  16.512 33.301 16.536 35.987 ;
     RECT  17.568 35.941 17.592 36.229 ;
     RECT  18.6 30.323 18.912 36.229 ;
     RECT  44.448 35.845 44.52 36.421 ;
     RECT  45.6 34.931 45.912 36.421 ;
     RECT  36.768 35.555 36.792 36.467 ;
     RECT  6.864 35.317 8.112 36.515 ;
     RECT  18.6 36.229 19.272 36.515 ;
     RECT  38.928 35.989 38.952 36.899 ;
     RECT  7.2 36.515 8.112 36.947 ;
     RECT  42.288 35.509 42.744 36.947 ;
     RECT  11.376 35.989 11.4 36.949 ;
     RECT  10.848 36.949 11.4 36.995 ;
     RECT  16.944 36.229 17.592 37.091 ;
     RECT  26.544 32.725 26.76 37.091 ;
     RECT  32.064 35.749 32.28 37.091 ;
     RECT  23.328 34.117 24.312 37.475 ;
     RECT  29.4 35.939 30.696 37.477 ;
     RECT  21.12 34.403 22.104 37.573 ;
     RECT  42.72 36.947 42.744 37.573 ;
     RECT  10.848 36.995 10.872 37.667 ;
     RECT  12.48 35.125 13.944 37.667 ;
     RECT  32.064 37.091 32.088 37.811 ;
     RECT  16.992 37.091 17.592 37.861 ;
     RECT  18.6 36.515 18.912 37.861 ;
     RECT  26.544 37.091 26.568 38.053 ;
     RECT  37.872 33.779 37.896 38.195 ;
     RECT  42.72 37.573 43.32 38.195 ;
     RECT  44.448 36.421 45.912 38.675 ;
     RECT  25.632 38.053 26.568 38.677 ;
     RECT  40.2 35.027 41.16 38.723 ;
     RECT  7.8 36.947 8.112 38.725 ;
     RECT  6.288 38.101 6.312 38.771 ;
     RECT  25.632 38.677 26.76 38.819 ;
     RECT  16.992 37.861 18.912 38.867 ;
     RECT  16.992 38.867 17.016 39.061 ;
     RECT  29.4 37.477 30.744 39.253 ;
     RECT  42.72 38.195 42.744 39.301 ;
     RECT  39.12 38.533 39.144 39.347 ;
     RECT  23.808 37.475 24.312 39.733 ;
     RECT  7.8 38.725 8.232 39.779 ;
     RECT  34.272 34.739 35.112 39.781 ;
     RECT  42.72 39.301 42.984 39.923 ;
     RECT  37.008 39.301 37.032 40.163 ;
     RECT  18.096 38.867 18.912 40.165 ;
     RECT  26.544 38.819 26.76 40.213 ;
     RECT  20.688 37.573 22.104 40.259 ;
     RECT  16.128 39.061 17.016 40.499 ;
     RECT  23.376 39.733 24.312 40.597 ;
     RECT  23.376 40.597 25.176 40.837 ;
     RECT  42.72 39.923 42.744 40.933 ;
     RECT  23.376 40.837 25.368 40.979 ;
     RECT  33.6 39.781 35.112 40.979 ;
     RECT  18.096 40.165 19.08 40.981 ;
     RECT  38.112 38.725 38.136 40.981 ;
     RECT  23.376 40.979 25.176 41.027 ;
     RECT  18.096 40.981 19.128 41.077 ;
     RECT  34.272 40.979 35.112 41.269 ;
     RECT  29.4 39.253 31.32 41.651 ;
     RECT  38.112 40.981 38.76 41.651 ;
     RECT  26.448 40.213 26.76 41.699 ;
     RECT  29.4 41.651 29.712 41.749 ;
     RECT  34.272 41.269 36.024 41.795 ;
     RECT  38.736 41.651 38.76 41.795 ;
     RECT  21.12 40.259 22.104 41.891 ;
     RECT  11.808 39.637 11.832 41.989 ;
     RECT  23.376 41.027 24.312 42.181 ;
     RECT  10.896 41.989 11.832 42.227 ;
     RECT  18.096 41.077 19.224 42.227 ;
     RECT  31.296 41.651 31.32 42.227 ;
     RECT  40.2 38.723 40.776 42.227 ;
     RECT  23.376 42.181 25.128 42.323 ;
     RECT  23.904 42.323 25.128 42.371 ;
     RECT  28.416 41.749 29.712 42.419 ;
     RECT  16.128 40.499 16.872 42.803 ;
     RECT  22.08 41.891 22.104 42.803 ;
     RECT  42.72 40.933 43.464 42.803 ;
     RECT  38.304 42.757 38.328 43.043 ;
     RECT  10.896 42.227 10.92 43.331 ;
     RECT  26.448 41.699 26.472 43.523 ;
     RECT  18.096 42.227 19.08 43.573 ;
     RECT  9.552 43.285 9.576 43.907 ;
     RECT  23.904 42.371 25.08 43.955 ;
     RECT  16.848 42.803 16.872 44.051 ;
     RECT  13.2 37.667 13.944 44.101 ;
     RECT  24 43.955 25.08 45.011 ;
     RECT  16.8 44.437 16.824 45.251 ;
     RECT  33.216 43.861 33.24 45.301 ;
     RECT  34.272 41.795 35.112 45.301 ;
     RECT  32.16 43.285 32.184 45.347 ;
     RECT  18.096 43.573 19.176 45.349 ;
     RECT  7.8 39.779 8.112 45.541 ;
     RECT  26.544 43.525 27.384 45.541 ;
     RECT  37.2 43.285 37.224 45.541 ;
     RECT  25.968 45.541 27.384 45.587 ;
     RECT  37.2 45.541 37.992 46.117 ;
     RECT  24 45.011 24.408 46.213 ;
     RECT  25.968 45.587 26.568 46.213 ;
     RECT  24 46.213 26.568 46.259 ;
     RECT  18.096 45.349 19.32 46.261 ;
     RECT  29.4 42.419 29.712 46.645 ;
     RECT  18.096 46.261 19.896 46.739 ;
     RECT  6.864 45.541 8.112 46.787 ;
     RECT  21.6 45.685 21.624 46.787 ;
     RECT  33.216 45.301 35.112 47.171 ;
     RECT  33.504 47.171 35.112 47.317 ;
     RECT  37.104 46.117 37.992 47.363 ;
     RECT  80.112 42.853 80.136 47.603 ;
     RECT  13.2 44.101 13.992 47.653 ;
     RECT  33.504 47.317 35.208 47.843 ;
     RECT  44.928 38.675 45.912 47.891 ;
     RECT  42.72 42.803 42.984 48.421 ;
     RECT  33.6 47.843 35.208 48.467 ;
     RECT  37.104 47.363 37.128 48.515 ;
     RECT  24 46.259 25.128 48.661 ;
     RECT  16.08 46.117 16.104 48.707 ;
     RECT  24 48.661 25.416 48.707 ;
     RECT  13.2 47.653 14.232 48.803 ;
     RECT  28.992 46.645 29.712 49.043 ;
     RECT  32.16 48.421 32.184 49.091 ;
     RECT  29.088 49.043 29.712 49.139 ;
     RECT  29.4 49.139 29.712 49.525 ;
     RECT  33.6 48.467 35.112 49.619 ;
     RECT  29.4 49.525 29.976 50.101 ;
     RECT  25.392 48.707 25.416 50.147 ;
     RECT  37.056 49.525 37.08 50.531 ;
     RECT  18.096 46.739 19.32 50.533 ;
     RECT  26.544 46.259 26.568 50.533 ;
     RECT  26.544 50.533 26.856 50.581 ;
     RECT  28.896 50.101 29.976 50.627 ;
     RECT  24 48.707 24.312 50.629 ;
     RECT  26.544 50.581 27.768 50.723 ;
     RECT  17.76 50.533 19.32 50.771 ;
     RECT  26.832 50.723 27.768 50.915 ;
     RECT  34.272 49.619 35.112 51.205 ;
     RECT  34.272 51.205 35.928 51.491 ;
     RECT  27.744 50.915 27.768 51.637 ;
     RECT  28.896 50.627 29.88 51.637 ;
     RECT  17.76 50.771 18.912 51.683 ;
     RECT  27.744 51.637 29.88 51.923 ;
     RECT  31.776 50.149 31.8 52.067 ;
     RECT  34.8 51.491 35.928 52.597 ;
     RECT  28.464 51.923 29.88 52.643 ;
     RECT  34.8 52.597 36.168 52.643 ;
     RECT  34.8 52.643 35.112 52.789 ;
     RECT  23.04 50.629 24.312 53.075 ;
     RECT  26.784 52.837 26.808 53.075 ;
     RECT  20.544 51.829 20.568 53.123 ;
     RECT  34.08 52.789 35.112 53.603 ;
     RECT  29.4 52.643 29.88 53.797 ;
     RECT  6.528 47.845 6.552 53.843 ;
     RECT  29.4 53.797 30.168 54.227 ;
     RECT  36.144 52.643 36.168 82.451 ;
     RECT  42.72 48.421 43.032 82.691 ;
     RECT  2.4 34.931 2.712 84.249 ;
     RECT  7.8 46.787 8.112 84.249 ;
     RECT  13.2 48.803 13.512 84.249 ;
     RECT  18.6 51.683 18.912 84.249 ;
     RECT  24 53.075 24.312 84.249 ;
     RECT  29.4 54.227 29.712 84.249 ;
     RECT  34.8 53.603 35.112 84.249 ;
     RECT  40.2 42.227 40.512 84.249 ;
     RECT  45.6 47.891 45.912 84.249 ;
     RECT  51 1.763 51.312 84.249 ;
     RECT  56.4 4.163 56.712 84.249 ;
     RECT  61.8 2.151 62.112 84.249 ;
     RECT  67.2 2.151 67.512 84.249 ;
     RECT  72.6 2.151 72.912 84.249 ;
     RECT  78 2.151 78.312 84.249 ;
     RECT  83.4 2.151 83.712 84.249 ;
     RECT  2.4 84.249 2.52 84.263 ;
     RECT  7.8 84.249 7.92 84.263 ;
     RECT  13.2 84.249 13.32 84.263 ;
     RECT  18.6 84.249 18.72 84.263 ;
     RECT  24 84.249 24.12 84.263 ;
     RECT  29.4 84.249 29.52 84.263 ;
     RECT  34.8 84.249 34.92 84.263 ;
     RECT  40.2 84.249 40.32 84.263 ;
     RECT  45.6 84.249 45.72 84.263 ;
     RECT  51 84.249 51.12 84.263 ;
     RECT  56.4 84.249 56.52 84.263 ;
     RECT  61.8 84.249 61.92 84.263 ;
     RECT  67.2 84.249 67.32 84.263 ;
     RECT  72.6 84.249 72.72 84.263 ;
     RECT  78 84.249 78.12 84.263 ;
     RECT  83.4 84.249 83.52 84.263 ;
     RECT  42.72 82.691 42.744 84.325 ;
     RECT  42.72 84.325 43.704 86.352 ;
     RECT  29.4 0.611 29.52 2.137 ;
     RECT  33.72 0.611 35.424 1.763 ;
     RECT  38.328 0.611 39.456 1.763 ;
     RECT  40.632 0.611 41.76 1.763 ;
     RECT  42.36 0.611 43.488 1.763 ;
     RECT  44.088 0.611 45.216 1.763 ;
     RECT  45.24 0.611 46.368 1.763 ;
     RECT  46.392 0.611 47.52 1.763 ;
     RECT  48.696 0.611 49.824 1.763 ;
     RECT  51.576 0.611 52.704 1.763 ;
     RECT  34.8 1.763 35.112 2.137 ;
     RECT  39.6 1.763 40.2 2.821 ;
     RECT  43.776 1.763 43.8 3.205 ;
     RECT  45.6 1.763 45.912 2.137 ;
     RECT  42.408 3.397 43.776 4.595 ;
     RECT  39.6 4.115 40.2 5.125 ;
     RECT  33.288 4.501 34.8 6.323 ;
     RECT  45.912 4.501 47.232 5.219 ;
     RECT  47.256 4.501 48.48 5.219 ;
     RECT  39 5.125 40.2 12.085 ;
     RECT  37.32 8.389 38.496 8.435 ;
     RECT  24.312 9.349 25.68 9.637 ;
     RECT  31.704 9.493 32.976 9.539 ;
     RECT  24.312 9.637 25.488 11.413 ;
     RECT  35.112 10.213 36.48 10.741 ;
     RECT  29.712 10.355 31.392 11.749 ;
     RECT  16.344 10.789 17.856 11.411 ;
     RECT  11.688 11.125 13.2 13.139 ;
     RECT  16.704 11.411 17.856 12.709 ;
     RECT  30.312 11.749 31.392 13.139 ;
     RECT  39.048 12.085 40.2 18.851 ;
     RECT  16.728 12.709 17.856 12.755 ;
     RECT  16.728 12.755 18.096 13.811 ;
     RECT  24.312 12.755 25.488 14.867 ;
     RECT  11.952 13.139 13.2 13.909 ;
     RECT  16.728 13.811 18.48 14.675 ;
     RECT  11.976 13.909 13.2 16.595 ;
     RECT  35.832 14.483 36.816 15.443 ;
     RECT  16.728 14.675 18.6 14.917 ;
     RECT  8.112 14.917 9.36 17.461 ;
     RECT  17.208 14.917 18.6 17.123 ;
     RECT  16.128 14.963 16.704 15.925 ;
     RECT  15.384 15.925 16.704 17.029 ;
     RECT  22.872 16.981 24 19.235 ;
     RECT  15.384 17.029 16.608 17.171 ;
     RECT  24.312 17.029 25.728 17.077 ;
     RECT  24.744 17.077 25.728 17.699 ;
     RECT  18.48 17.123 18.6 17.461 ;
     RECT  15.936 17.171 16.608 17.461 ;
     RECT  38.784 18.179 39.024 18.851 ;
     RECT  38.784 18.851 40.2 19.669 ;
     RECT  13.512 18.947 13.608 20.197 ;
     RECT  38.808 19.669 40.2 20.579 ;
     RECT  31.8 19.765 32.928 20.339 ;
     RECT  31.704 20.339 32.928 21.251 ;
     RECT  40.512 20.485 41.856 21.733 ;
     RECT  8.568 20.531 9.936 21.011 ;
     RECT  29.712 20.677 30.816 21.971 ;
     RECT  9.96 20.725 11.376 22.259 ;
     RECT  40.632 21.733 41.856 22.883 ;
     RECT  29.712 21.971 29.976 22.549 ;
     RECT  9.96 22.259 10.968 23.125 ;
     RECT  40.512 22.883 41.856 24.181 ;
     RECT  44.568 23.029 45.6 23.893 ;
     RECT  9.96 23.125 10.944 24.469 ;
     RECT  30.696 23.845 31.68 23.893 ;
     RECT  40.776 24.181 41.856 24.947 ;
     RECT  27.336 24.325 28.512 24.803 ;
     RECT  27.336 24.803 28.608 25.667 ;
     RECT  40.632 24.947 41.856 26.579 ;
     RECT  8.568 25.045 9.936 25.715 ;
     RECT  17.352 25.045 18.6 29.029 ;
     RECT  25.032 25.237 26.304 26.099 ;
     RECT  20.664 25.573 21.984 26.243 ;
     RECT  25.032 26.099 26.352 26.821 ;
     RECT  21.504 26.243 21.984 26.773 ;
     RECT  40.512 26.579 41.856 27.395 ;
     RECT  2.712 26.819 3.432 28.165 ;
     RECT  25.08 26.821 26.352 27.253 ;
     RECT  25.32 27.253 26.352 28.693 ;
     RECT  45.912 27.347 46.2 28.453 ;
     RECT  40.512 27.395 40.632 27.829 ;
     RECT  28.056 28.069 29.4 28.885 ;
     RECT  2.712 28.165 3.936 29.651 ;
     RECT  33.288 28.357 34.8 29.459 ;
     RECT  10.296 28.451 10.872 28.693 ;
     RECT  10.296 28.693 11.568 30.133 ;
     RECT  11.592 28.693 12.912 29.221 ;
     RECT  13.512 28.933 14.976 29.221 ;
     RECT  22.968 28.933 24 32.195 ;
     RECT  43.368 28.933 44.784 29.123 ;
     RECT  28.056 29.411 29.4 29.603 ;
     RECT  32.472 29.459 34.8 30.517 ;
     RECT  31.176 29.555 32.16 30.803 ;
     RECT  27.432 29.603 29.4 30.565 ;
     RECT  25.704 29.747 26.736 30.275 ;
     RECT  10.296 30.133 11.52 31.187 ;
     RECT  24.312 30.227 25.296 30.803 ;
     RECT  25.32 30.275 26.736 30.803 ;
     RECT  17.256 30.323 18.6 31.955 ;
     RECT  38.808 30.373 40.2 30.755 ;
     RECT  32.472 30.517 33.6 30.563 ;
     RECT  33.624 30.517 34.8 30.659 ;
     RECT  32.184 30.563 33.6 30.659 ;
     RECT  27.96 30.565 29.4 31.907 ;
     RECT  30.696 30.803 32.16 31.139 ;
     RECT  30.696 31.139 30.984 32.389 ;
     RECT  40.512 31.955 40.632 33.109 ;
     RECT  24.312 33.349 25.536 34.307 ;
     RECT  25.56 33.349 26.544 34.307 ;
     RECT  30.696 33.683 30.984 34.741 ;
     RECT  37.824 33.683 37.872 34.213 ;
     RECT  44.52 33.779 45.6 36.421 ;
     RECT  22.104 34.117 23.328 37.475 ;
     RECT  41.544 34.165 42.72 35.027 ;
     RECT  36.888 34.213 37.872 35.555 ;
     RECT  30.696 34.741 32.064 37.477 ;
     RECT  44.448 34.835 44.496 35.845 ;
     RECT  41.16 35.027 42.72 35.509 ;
     RECT  41.16 35.509 42.288 36.947 ;
     RECT  36.792 35.555 37.872 36.467 ;
     RECT  16.536 35.941 17.568 35.987 ;
     RECT  17.592 35.941 18.6 37.861 ;
     RECT  16.944 35.987 17.568 36.229 ;
     RECT  11.4 35.989 12.48 36.995 ;
     RECT  37.896 35.989 38.928 36.899 ;
     RECT  38.952 35.989 40.2 36.899 ;
     RECT  7.2 36.947 7.8 38.101 ;
     RECT  30.744 37.477 32.064 37.811 ;
     RECT  43.32 37.573 44.448 38.195 ;
     RECT  30.744 37.811 31.32 39.253 ;
     RECT  24.312 38.053 25.632 38.819 ;
     RECT  6.312 38.101 7.8 38.771 ;
     RECT  37.872 38.195 37.896 38.533 ;
     RECT  42.744 38.195 44.448 38.675 ;
     RECT  37.872 38.533 39.12 38.725 ;
     RECT  39.144 38.533 40.2 39.347 ;
     RECT  42.744 38.675 42.984 39.301 ;
     RECT  37.872 38.725 38.112 39.301 ;
     RECT  38.136 38.725 39.12 39.347 ;
     RECT  26.448 38.819 26.544 40.213 ;
     RECT  17.016 38.867 18.096 40.499 ;
     RECT  37.032 39.301 38.112 40.163 ;
     RECT  11.832 39.637 13.2 42.227 ;
     RECT  22.104 39.733 23.376 42.323 ;
     RECT  42.744 39.923 42.984 40.933 ;
     RECT  16.872 40.499 18.096 44.051 ;
     RECT  25.176 40.597 26.448 40.837 ;
     RECT  25.368 40.837 26.448 40.979 ;
     RECT  43.464 40.933 44.928 42.803 ;
     RECT  25.176 40.979 26.448 41.027 ;
     RECT  38.76 40.981 40.2 41.795 ;
     RECT  24.312 41.027 26.448 42.181 ;
     RECT  38.304 41.651 38.736 41.795 ;
     RECT  38.304 41.795 38.328 42.757 ;
     RECT  25.128 42.181 26.448 42.371 ;
     RECT  19.08 42.227 19.176 43.573 ;
     RECT  25.08 42.371 26.448 43.523 ;
     RECT  8.112 43.285 9.552 43.907 ;
     RECT  9.576 43.285 10.896 43.331 ;
     RECT  25.08 43.523 26.472 43.525 ;
     RECT  25.08 43.525 26.544 45.011 ;
     RECT  32.184 43.861 33.216 45.347 ;
     RECT  33.24 43.861 34.272 45.301 ;
     RECT  16.848 44.051 18.096 44.437 ;
     RECT  16.824 44.437 18.096 45.251 ;
     RECT  24.408 45.011 26.544 45.541 ;
     RECT  24.408 45.541 25.968 46.213 ;
     RECT  25.128 46.259 26.544 48.661 ;
     RECT  6.864 46.787 7.8 47.845 ;
     RECT  33.216 47.171 33.504 47.843 ;
     RECT  33.216 47.843 33.6 48.421 ;
     RECT  6.552 47.845 7.8 53.843 ;
     RECT  32.184 48.421 33.6 49.091 ;
     RECT  25.416 48.661 26.544 50.147 ;
     RECT  24.312 48.707 25.392 50.147 ;
     RECT  28.992 49.043 29.088 49.139 ;
     RECT  28.992 49.139 29.4 50.101 ;
     RECT  27.768 50.581 28.896 51.637 ;
     RECT  34.272 51.491 34.8 52.789 ;
     RECT  35.112 52.643 36.144 82.451 ;
  END
END ot_hbm_program_block_ready_pin
END LIBRARY
